VERSION 5.7 ;
BUSBITCHARS "[]" ;
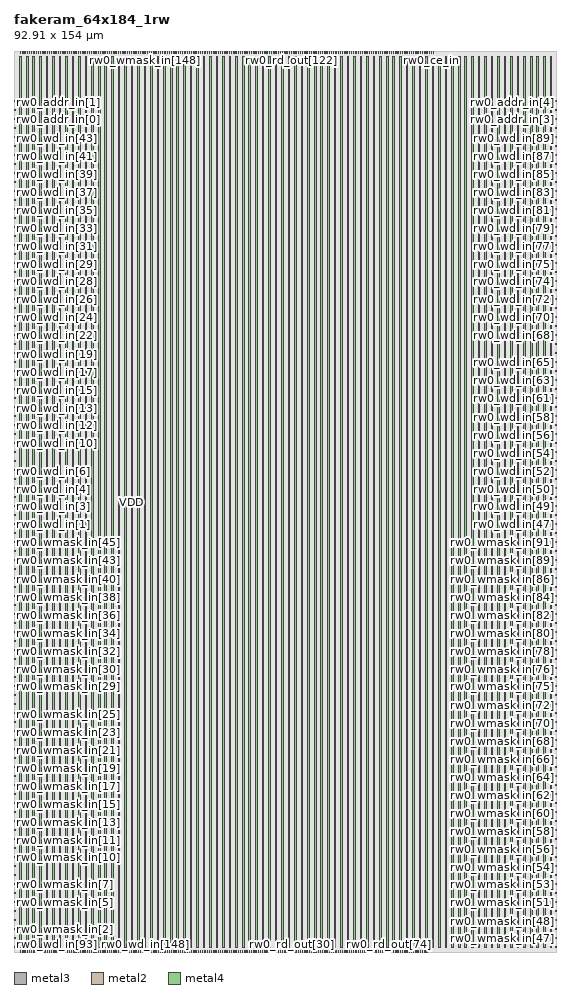
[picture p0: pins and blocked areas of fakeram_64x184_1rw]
MACRO fakeram_64x184_1rw
  FOREIGN fakeram_64x184_1rw 0 0 ;
  SYMMETRY X Y R90 ;
  SIZE 92.910 BY 154.000 ;
  CLASS BLOCK ;
  PIN rw0_wmask_in[0]
    DIRECTION INPUT ;
    USE SIGNAL ;
    SHAPE ABUTMENT ;
    PORT
      LAYER metal3 ;
      RECT 0.000 0.805 0.210 0.875 ;
    END
  END rw0_wmask_in[0]
  PIN rw0_wmask_in[1]
    DIRECTION INPUT ;
    USE SIGNAL ;
    SHAPE ABUTMENT ;
    PORT
      LAYER metal3 ;
      RECT 0.000 2.345 0.210 2.415 ;
    END
  END rw0_wmask_in[1]
  PIN rw0_wmask_in[2]
    DIRECTION INPUT ;
    USE SIGNAL ;
    SHAPE ABUTMENT ;
    PORT
      LAYER metal3 ;
      RECT 0.000 3.885 0.210 3.955 ;
    END
  END rw0_wmask_in[2]
  PIN rw0_wmask_in[3]
    DIRECTION INPUT ;
    USE SIGNAL ;
    SHAPE ABUTMENT ;
    PORT
      LAYER metal3 ;
      RECT 0.000 5.425 0.210 5.495 ;
    END
  END rw0_wmask_in[3]
  PIN rw0_wmask_in[4]
    DIRECTION INPUT ;
    USE SIGNAL ;
    SHAPE ABUTMENT ;
    PORT
      LAYER metal3 ;
      RECT 0.000 6.965 0.210 7.035 ;
    END
  END rw0_wmask_in[4]
  PIN rw0_wmask_in[5]
    DIRECTION INPUT ;
    USE SIGNAL ;
    SHAPE ABUTMENT ;
    PORT
      LAYER metal3 ;
      RECT 0.000 8.505 0.210 8.575 ;
    END
  END rw0_wmask_in[5]
  PIN rw0_wmask_in[6]
    DIRECTION INPUT ;
    USE SIGNAL ;
    SHAPE ABUTMENT ;
    PORT
      LAYER metal3 ;
      RECT 0.000 10.045 0.210 10.115 ;
    END
  END rw0_wmask_in[6]
  PIN rw0_wmask_in[7]
    DIRECTION INPUT ;
    USE SIGNAL ;
    SHAPE ABUTMENT ;
    PORT
      LAYER metal3 ;
      RECT 0.000 11.585 0.210 11.655 ;
    END
  END rw0_wmask_in[7]
  PIN rw0_wmask_in[8]
    DIRECTION INPUT ;
    USE SIGNAL ;
    SHAPE ABUTMENT ;
    PORT
      LAYER metal3 ;
      RECT 0.000 13.125 0.210 13.195 ;
    END
  END rw0_wmask_in[8]
  PIN rw0_wmask_in[9]
    DIRECTION INPUT ;
    USE SIGNAL ;
    SHAPE ABUTMENT ;
    PORT
      LAYER metal3 ;
      RECT 0.000 14.665 0.210 14.735 ;
    END
  END rw0_wmask_in[9]
  PIN rw0_wmask_in[10]
    DIRECTION INPUT ;
    USE SIGNAL ;
    SHAPE ABUTMENT ;
    PORT
      LAYER metal3 ;
      RECT 0.000 16.205 0.210 16.275 ;
    END
  END rw0_wmask_in[10]
  PIN rw0_wmask_in[11]
    DIRECTION INPUT ;
    USE SIGNAL ;
    SHAPE ABUTMENT ;
    PORT
      LAYER metal3 ;
      RECT 0.000 17.745 0.210 17.815 ;
    END
  END rw0_wmask_in[11]
  PIN rw0_wmask_in[12]
    DIRECTION INPUT ;
    USE SIGNAL ;
    SHAPE ABUTMENT ;
    PORT
      LAYER metal3 ;
      RECT 0.000 19.285 0.210 19.355 ;
    END
  END rw0_wmask_in[12]
  PIN rw0_wmask_in[13]
    DIRECTION INPUT ;
    USE SIGNAL ;
    SHAPE ABUTMENT ;
    PORT
      LAYER metal3 ;
      RECT 0.000 20.825 0.210 20.895 ;
    END
  END rw0_wmask_in[13]
  PIN rw0_wmask_in[14]
    DIRECTION INPUT ;
    USE SIGNAL ;
    SHAPE ABUTMENT ;
    PORT
      LAYER metal3 ;
      RECT 0.000 22.365 0.210 22.435 ;
    END
  END rw0_wmask_in[14]
  PIN rw0_wmask_in[15]
    DIRECTION INPUT ;
    USE SIGNAL ;
    SHAPE ABUTMENT ;
    PORT
      LAYER metal3 ;
      RECT 0.000 23.905 0.210 23.975 ;
    END
  END rw0_wmask_in[15]
  PIN rw0_wmask_in[16]
    DIRECTION INPUT ;
    USE SIGNAL ;
    SHAPE ABUTMENT ;
    PORT
      LAYER metal3 ;
      RECT 0.000 25.445 0.210 25.515 ;
    END
  END rw0_wmask_in[16]
  PIN rw0_wmask_in[17]
    DIRECTION INPUT ;
    USE SIGNAL ;
    SHAPE ABUTMENT ;
    PORT
      LAYER metal3 ;
      RECT 0.000 26.985 0.210 27.055 ;
    END
  END rw0_wmask_in[17]
  PIN rw0_wmask_in[18]
    DIRECTION INPUT ;
    USE SIGNAL ;
    SHAPE ABUTMENT ;
    PORT
      LAYER metal3 ;
      RECT 0.000 28.525 0.210 28.595 ;
    END
  END rw0_wmask_in[18]
  PIN rw0_wmask_in[19]
    DIRECTION INPUT ;
    USE SIGNAL ;
    SHAPE ABUTMENT ;
    PORT
      LAYER metal3 ;
      RECT 0.000 30.065 0.210 30.135 ;
    END
  END rw0_wmask_in[19]
  PIN rw0_wmask_in[20]
    DIRECTION INPUT ;
    USE SIGNAL ;
    SHAPE ABUTMENT ;
    PORT
      LAYER metal3 ;
      RECT 0.000 31.605 0.210 31.675 ;
    END
  END rw0_wmask_in[20]
  PIN rw0_wmask_in[21]
    DIRECTION INPUT ;
    USE SIGNAL ;
    SHAPE ABUTMENT ;
    PORT
      LAYER metal3 ;
      RECT 0.000 33.145 0.210 33.215 ;
    END
  END rw0_wmask_in[21]
  PIN rw0_wmask_in[22]
    DIRECTION INPUT ;
    USE SIGNAL ;
    SHAPE ABUTMENT ;
    PORT
      LAYER metal3 ;
      RECT 0.000 34.685 0.210 34.755 ;
    END
  END rw0_wmask_in[22]
  PIN rw0_wmask_in[23]
    DIRECTION INPUT ;
    USE SIGNAL ;
    SHAPE ABUTMENT ;
    PORT
      LAYER metal3 ;
      RECT 0.000 36.225 0.210 36.295 ;
    END
  END rw0_wmask_in[23]
  PIN rw0_wmask_in[24]
    DIRECTION INPUT ;
    USE SIGNAL ;
    SHAPE ABUTMENT ;
    PORT
      LAYER metal3 ;
      RECT 0.000 37.765 0.210 37.835 ;
    END
  END rw0_wmask_in[24]
  PIN rw0_wmask_in[25]
    DIRECTION INPUT ;
    USE SIGNAL ;
    SHAPE ABUTMENT ;
    PORT
      LAYER metal3 ;
      RECT 0.000 39.305 0.210 39.375 ;
    END
  END rw0_wmask_in[25]
  PIN rw0_wmask_in[26]
    DIRECTION INPUT ;
    USE SIGNAL ;
    SHAPE ABUTMENT ;
    PORT
      LAYER metal3 ;
      RECT 0.000 40.845 0.210 40.915 ;
    END
  END rw0_wmask_in[26]
  PIN rw0_wmask_in[27]
    DIRECTION INPUT ;
    USE SIGNAL ;
    SHAPE ABUTMENT ;
    PORT
      LAYER metal3 ;
      RECT 0.000 42.385 0.210 42.455 ;
    END
  END rw0_wmask_in[27]
  PIN rw0_wmask_in[28]
    DIRECTION INPUT ;
    USE SIGNAL ;
    SHAPE ABUTMENT ;
    PORT
      LAYER metal3 ;
      RECT 0.000 43.925 0.210 43.995 ;
    END
  END rw0_wmask_in[28]
  PIN rw0_wmask_in[29]
    DIRECTION INPUT ;
    USE SIGNAL ;
    SHAPE ABUTMENT ;
    PORT
      LAYER metal3 ;
      RECT 0.000 45.465 0.210 45.535 ;
    END
  END rw0_wmask_in[29]
  PIN rw0_wmask_in[30]
    DIRECTION INPUT ;
    USE SIGNAL ;
    SHAPE ABUTMENT ;
    PORT
      LAYER metal3 ;
      RECT 0.000 47.005 0.210 47.075 ;
    END
  END rw0_wmask_in[30]
  PIN rw0_wmask_in[31]
    DIRECTION INPUT ;
    USE SIGNAL ;
    SHAPE ABUTMENT ;
    PORT
      LAYER metal3 ;
      RECT 0.000 48.545 0.210 48.615 ;
    END
  END rw0_wmask_in[31]
  PIN rw0_wmask_in[32]
    DIRECTION INPUT ;
    USE SIGNAL ;
    SHAPE ABUTMENT ;
    PORT
      LAYER metal3 ;
      RECT 0.000 50.085 0.210 50.155 ;
    END
  END rw0_wmask_in[32]
  PIN rw0_wmask_in[33]
    DIRECTION INPUT ;
    USE SIGNAL ;
    SHAPE ABUTMENT ;
    PORT
      LAYER metal3 ;
      RECT 0.000 51.625 0.210 51.695 ;
    END
  END rw0_wmask_in[33]
  PIN rw0_wmask_in[34]
    DIRECTION INPUT ;
    USE SIGNAL ;
    SHAPE ABUTMENT ;
    PORT
      LAYER metal3 ;
      RECT 0.000 53.165 0.210 53.235 ;
    END
  END rw0_wmask_in[34]
  PIN rw0_wmask_in[35]
    DIRECTION INPUT ;
    USE SIGNAL ;
    SHAPE ABUTMENT ;
    PORT
      LAYER metal3 ;
      RECT 0.000 54.705 0.210 54.775 ;
    END
  END rw0_wmask_in[35]
  PIN rw0_wmask_in[36]
    DIRECTION INPUT ;
    USE SIGNAL ;
    SHAPE ABUTMENT ;
    PORT
      LAYER metal3 ;
      RECT 0.000 56.245 0.210 56.315 ;
    END
  END rw0_wmask_in[36]
  PIN rw0_wmask_in[37]
    DIRECTION INPUT ;
    USE SIGNAL ;
    SHAPE ABUTMENT ;
    PORT
      LAYER metal3 ;
      RECT 0.000 57.785 0.210 57.855 ;
    END
  END rw0_wmask_in[37]
  PIN rw0_wmask_in[38]
    DIRECTION INPUT ;
    USE SIGNAL ;
    SHAPE ABUTMENT ;
    PORT
      LAYER metal3 ;
      RECT 0.000 59.325 0.210 59.395 ;
    END
  END rw0_wmask_in[38]
  PIN rw0_wmask_in[39]
    DIRECTION INPUT ;
    USE SIGNAL ;
    SHAPE ABUTMENT ;
    PORT
      LAYER metal3 ;
      RECT 0.000 60.865 0.210 60.935 ;
    END
  END rw0_wmask_in[39]
  PIN rw0_wmask_in[40]
    DIRECTION INPUT ;
    USE SIGNAL ;
    SHAPE ABUTMENT ;
    PORT
      LAYER metal3 ;
      RECT 0.000 62.405 0.210 62.475 ;
    END
  END rw0_wmask_in[40]
  PIN rw0_wmask_in[41]
    DIRECTION INPUT ;
    USE SIGNAL ;
    SHAPE ABUTMENT ;
    PORT
      LAYER metal3 ;
      RECT 0.000 63.945 0.210 64.015 ;
    END
  END rw0_wmask_in[41]
  PIN rw0_wmask_in[42]
    DIRECTION INPUT ;
    USE SIGNAL ;
    SHAPE ABUTMENT ;
    PORT
      LAYER metal3 ;
      RECT 0.000 65.485 0.210 65.555 ;
    END
  END rw0_wmask_in[42]
  PIN rw0_wmask_in[43]
    DIRECTION INPUT ;
    USE SIGNAL ;
    SHAPE ABUTMENT ;
    PORT
      LAYER metal3 ;
      RECT 0.000 67.025 0.210 67.095 ;
    END
  END rw0_wmask_in[43]
  PIN rw0_wmask_in[44]
    DIRECTION INPUT ;
    USE SIGNAL ;
    SHAPE ABUTMENT ;
    PORT
      LAYER metal3 ;
      RECT 0.000 68.565 0.210 68.635 ;
    END
  END rw0_wmask_in[44]
  PIN rw0_wmask_in[45]
    DIRECTION INPUT ;
    USE SIGNAL ;
    SHAPE ABUTMENT ;
    PORT
      LAYER metal3 ;
      RECT 0.000 70.105 0.210 70.175 ;
    END
  END rw0_wmask_in[45]
  PIN rw0_wmask_in[46]
    DIRECTION INPUT ;
    USE SIGNAL ;
    SHAPE ABUTMENT ;
    PORT
      LAYER metal3 ;
      RECT 92.700 0.805 92.910 0.875 ;
    END
  END rw0_wmask_in[46]
  PIN rw0_wmask_in[47]
    DIRECTION INPUT ;
    USE SIGNAL ;
    SHAPE ABUTMENT ;
    PORT
      LAYER metal3 ;
      RECT 92.700 2.345 92.910 2.415 ;
    END
  END rw0_wmask_in[47]
  PIN rw0_wmask_in[48]
    DIRECTION INPUT ;
    USE SIGNAL ;
    SHAPE ABUTMENT ;
    PORT
      LAYER metal3 ;
      RECT 92.700 3.885 92.910 3.955 ;
    END
  END rw0_wmask_in[48]
  PIN rw0_wmask_in[49]
    DIRECTION INPUT ;
    USE SIGNAL ;
    SHAPE ABUTMENT ;
    PORT
      LAYER metal3 ;
      RECT 92.700 5.425 92.910 5.495 ;
    END
  END rw0_wmask_in[49]
  PIN rw0_wmask_in[50]
    DIRECTION INPUT ;
    USE SIGNAL ;
    SHAPE ABUTMENT ;
    PORT
      LAYER metal3 ;
      RECT 92.700 6.965 92.910 7.035 ;
    END
  END rw0_wmask_in[50]
  PIN rw0_wmask_in[51]
    DIRECTION INPUT ;
    USE SIGNAL ;
    SHAPE ABUTMENT ;
    PORT
      LAYER metal3 ;
      RECT 92.700 8.505 92.910 8.575 ;
    END
  END rw0_wmask_in[51]
  PIN rw0_wmask_in[52]
    DIRECTION INPUT ;
    USE SIGNAL ;
    SHAPE ABUTMENT ;
    PORT
      LAYER metal3 ;
      RECT 92.700 10.045 92.910 10.115 ;
    END
  END rw0_wmask_in[52]
  PIN rw0_wmask_in[53]
    DIRECTION INPUT ;
    USE SIGNAL ;
    SHAPE ABUTMENT ;
    PORT
      LAYER metal3 ;
      RECT 92.700 11.585 92.910 11.655 ;
    END
  END rw0_wmask_in[53]
  PIN rw0_wmask_in[54]
    DIRECTION INPUT ;
    USE SIGNAL ;
    SHAPE ABUTMENT ;
    PORT
      LAYER metal3 ;
      RECT 92.700 13.125 92.910 13.195 ;
    END
  END rw0_wmask_in[54]
  PIN rw0_wmask_in[55]
    DIRECTION INPUT ;
    USE SIGNAL ;
    SHAPE ABUTMENT ;
    PORT
      LAYER metal3 ;
      RECT 92.700 14.665 92.910 14.735 ;
    END
  END rw0_wmask_in[55]
  PIN rw0_wmask_in[56]
    DIRECTION INPUT ;
    USE SIGNAL ;
    SHAPE ABUTMENT ;
    PORT
      LAYER metal3 ;
      RECT 92.700 16.205 92.910 16.275 ;
    END
  END rw0_wmask_in[56]
  PIN rw0_wmask_in[57]
    DIRECTION INPUT ;
    USE SIGNAL ;
    SHAPE ABUTMENT ;
    PORT
      LAYER metal3 ;
      RECT 92.700 17.745 92.910 17.815 ;
    END
  END rw0_wmask_in[57]
  PIN rw0_wmask_in[58]
    DIRECTION INPUT ;
    USE SIGNAL ;
    SHAPE ABUTMENT ;
    PORT
      LAYER metal3 ;
      RECT 92.700 19.285 92.910 19.355 ;
    END
  END rw0_wmask_in[58]
  PIN rw0_wmask_in[59]
    DIRECTION INPUT ;
    USE SIGNAL ;
    SHAPE ABUTMENT ;
    PORT
      LAYER metal3 ;
      RECT 92.700 20.825 92.910 20.895 ;
    END
  END rw0_wmask_in[59]
  PIN rw0_wmask_in[60]
    DIRECTION INPUT ;
    USE SIGNAL ;
    SHAPE ABUTMENT ;
    PORT
      LAYER metal3 ;
      RECT 92.700 22.365 92.910 22.435 ;
    END
  END rw0_wmask_in[60]
  PIN rw0_wmask_in[61]
    DIRECTION INPUT ;
    USE SIGNAL ;
    SHAPE ABUTMENT ;
    PORT
      LAYER metal3 ;
      RECT 92.700 23.905 92.910 23.975 ;
    END
  END rw0_wmask_in[61]
  PIN rw0_wmask_in[62]
    DIRECTION INPUT ;
    USE SIGNAL ;
    SHAPE ABUTMENT ;
    PORT
      LAYER metal3 ;
      RECT 92.700 25.445 92.910 25.515 ;
    END
  END rw0_wmask_in[62]
  PIN rw0_wmask_in[63]
    DIRECTION INPUT ;
    USE SIGNAL ;
    SHAPE ABUTMENT ;
    PORT
      LAYER metal3 ;
      RECT 92.700 26.985 92.910 27.055 ;
    END
  END rw0_wmask_in[63]
  PIN rw0_wmask_in[64]
    DIRECTION INPUT ;
    USE SIGNAL ;
    SHAPE ABUTMENT ;
    PORT
      LAYER metal3 ;
      RECT 92.700 28.525 92.910 28.595 ;
    END
  END rw0_wmask_in[64]
  PIN rw0_wmask_in[65]
    DIRECTION INPUT ;
    USE SIGNAL ;
    SHAPE ABUTMENT ;
    PORT
      LAYER metal3 ;
      RECT 92.700 30.065 92.910 30.135 ;
    END
  END rw0_wmask_in[65]
  PIN rw0_wmask_in[66]
    DIRECTION INPUT ;
    USE SIGNAL ;
    SHAPE ABUTMENT ;
    PORT
      LAYER metal3 ;
      RECT 92.700 31.605 92.910 31.675 ;
    END
  END rw0_wmask_in[66]
  PIN rw0_wmask_in[67]
    DIRECTION INPUT ;
    USE SIGNAL ;
    SHAPE ABUTMENT ;
    PORT
      LAYER metal3 ;
      RECT 92.700 33.145 92.910 33.215 ;
    END
  END rw0_wmask_in[67]
  PIN rw0_wmask_in[68]
    DIRECTION INPUT ;
    USE SIGNAL ;
    SHAPE ABUTMENT ;
    PORT
      LAYER metal3 ;
      RECT 92.700 34.685 92.910 34.755 ;
    END
  END rw0_wmask_in[68]
  PIN rw0_wmask_in[69]
    DIRECTION INPUT ;
    USE SIGNAL ;
    SHAPE ABUTMENT ;
    PORT
      LAYER metal3 ;
      RECT 92.700 36.225 92.910 36.295 ;
    END
  END rw0_wmask_in[69]
  PIN rw0_wmask_in[70]
    DIRECTION INPUT ;
    USE SIGNAL ;
    SHAPE ABUTMENT ;
    PORT
      LAYER metal3 ;
      RECT 92.700 37.765 92.910 37.835 ;
    END
  END rw0_wmask_in[70]
  PIN rw0_wmask_in[71]
    DIRECTION INPUT ;
    USE SIGNAL ;
    SHAPE ABUTMENT ;
    PORT
      LAYER metal3 ;
      RECT 92.700 39.305 92.910 39.375 ;
    END
  END rw0_wmask_in[71]
  PIN rw0_wmask_in[72]
    DIRECTION INPUT ;
    USE SIGNAL ;
    SHAPE ABUTMENT ;
    PORT
      LAYER metal3 ;
      RECT 92.700 40.845 92.910 40.915 ;
    END
  END rw0_wmask_in[72]
  PIN rw0_wmask_in[73]
    DIRECTION INPUT ;
    USE SIGNAL ;
    SHAPE ABUTMENT ;
    PORT
      LAYER metal3 ;
      RECT 92.700 42.385 92.910 42.455 ;
    END
  END rw0_wmask_in[73]
  PIN rw0_wmask_in[74]
    DIRECTION INPUT ;
    USE SIGNAL ;
    SHAPE ABUTMENT ;
    PORT
      LAYER metal3 ;
      RECT 92.700 43.925 92.910 43.995 ;
    END
  END rw0_wmask_in[74]
  PIN rw0_wmask_in[75]
    DIRECTION INPUT ;
    USE SIGNAL ;
    SHAPE ABUTMENT ;
    PORT
      LAYER metal3 ;
      RECT 92.700 45.465 92.910 45.535 ;
    END
  END rw0_wmask_in[75]
  PIN rw0_wmask_in[76]
    DIRECTION INPUT ;
    USE SIGNAL ;
    SHAPE ABUTMENT ;
    PORT
      LAYER metal3 ;
      RECT 92.700 47.005 92.910 47.075 ;
    END
  END rw0_wmask_in[76]
  PIN rw0_wmask_in[77]
    DIRECTION INPUT ;
    USE SIGNAL ;
    SHAPE ABUTMENT ;
    PORT
      LAYER metal3 ;
      RECT 92.700 48.545 92.910 48.615 ;
    END
  END rw0_wmask_in[77]
  PIN rw0_wmask_in[78]
    DIRECTION INPUT ;
    USE SIGNAL ;
    SHAPE ABUTMENT ;
    PORT
      LAYER metal3 ;
      RECT 92.700 50.085 92.910 50.155 ;
    END
  END rw0_wmask_in[78]
  PIN rw0_wmask_in[79]
    DIRECTION INPUT ;
    USE SIGNAL ;
    SHAPE ABUTMENT ;
    PORT
      LAYER metal3 ;
      RECT 92.700 51.625 92.910 51.695 ;
    END
  END rw0_wmask_in[79]
  PIN rw0_wmask_in[80]
    DIRECTION INPUT ;
    USE SIGNAL ;
    SHAPE ABUTMENT ;
    PORT
      LAYER metal3 ;
      RECT 92.700 53.165 92.910 53.235 ;
    END
  END rw0_wmask_in[80]
  PIN rw0_wmask_in[81]
    DIRECTION INPUT ;
    USE SIGNAL ;
    SHAPE ABUTMENT ;
    PORT
      LAYER metal3 ;
      RECT 92.700 54.705 92.910 54.775 ;
    END
  END rw0_wmask_in[81]
  PIN rw0_wmask_in[82]
    DIRECTION INPUT ;
    USE SIGNAL ;
    SHAPE ABUTMENT ;
    PORT
      LAYER metal3 ;
      RECT 92.700 56.245 92.910 56.315 ;
    END
  END rw0_wmask_in[82]
  PIN rw0_wmask_in[83]
    DIRECTION INPUT ;
    USE SIGNAL ;
    SHAPE ABUTMENT ;
    PORT
      LAYER metal3 ;
      RECT 92.700 57.785 92.910 57.855 ;
    END
  END rw0_wmask_in[83]
  PIN rw0_wmask_in[84]
    DIRECTION INPUT ;
    USE SIGNAL ;
    SHAPE ABUTMENT ;
    PORT
      LAYER metal3 ;
      RECT 92.700 59.325 92.910 59.395 ;
    END
  END rw0_wmask_in[84]
  PIN rw0_wmask_in[85]
    DIRECTION INPUT ;
    USE SIGNAL ;
    SHAPE ABUTMENT ;
    PORT
      LAYER metal3 ;
      RECT 92.700 60.865 92.910 60.935 ;
    END
  END rw0_wmask_in[85]
  PIN rw0_wmask_in[86]
    DIRECTION INPUT ;
    USE SIGNAL ;
    SHAPE ABUTMENT ;
    PORT
      LAYER metal3 ;
      RECT 92.700 62.405 92.910 62.475 ;
    END
  END rw0_wmask_in[86]
  PIN rw0_wmask_in[87]
    DIRECTION INPUT ;
    USE SIGNAL ;
    SHAPE ABUTMENT ;
    PORT
      LAYER metal3 ;
      RECT 92.700 63.945 92.910 64.015 ;
    END
  END rw0_wmask_in[87]
  PIN rw0_wmask_in[88]
    DIRECTION INPUT ;
    USE SIGNAL ;
    SHAPE ABUTMENT ;
    PORT
      LAYER metal3 ;
      RECT 92.700 65.485 92.910 65.555 ;
    END
  END rw0_wmask_in[88]
  PIN rw0_wmask_in[89]
    DIRECTION INPUT ;
    USE SIGNAL ;
    SHAPE ABUTMENT ;
    PORT
      LAYER metal3 ;
      RECT 92.700 67.025 92.910 67.095 ;
    END
  END rw0_wmask_in[89]
  PIN rw0_wmask_in[90]
    DIRECTION INPUT ;
    USE SIGNAL ;
    SHAPE ABUTMENT ;
    PORT
      LAYER metal3 ;
      RECT 92.700 68.565 92.910 68.635 ;
    END
  END rw0_wmask_in[90]
  PIN rw0_wmask_in[91]
    DIRECTION INPUT ;
    USE SIGNAL ;
    SHAPE ABUTMENT ;
    PORT
      LAYER metal3 ;
      RECT 92.700 70.105 92.910 70.175 ;
    END
  END rw0_wmask_in[91]
  PIN rw0_wmask_in[92]
    DIRECTION INPUT ;
    USE SIGNAL ;
    SHAPE ABUTMENT ;
    PORT
      LAYER metal2 ;
      RECT 1.105 153.790 1.175 154.000 ;
    END
  END rw0_wmask_in[92]
  PIN rw0_wmask_in[93]
    DIRECTION INPUT ;
    USE SIGNAL ;
    SHAPE ABUTMENT ;
    PORT
      LAYER metal2 ;
      RECT 1.485 153.790 1.555 154.000 ;
    END
  END rw0_wmask_in[93]
  PIN rw0_wmask_in[94]
    DIRECTION INPUT ;
    USE SIGNAL ;
    SHAPE ABUTMENT ;
    PORT
      LAYER metal2 ;
      RECT 1.865 153.790 1.935 154.000 ;
    END
  END rw0_wmask_in[94]
  PIN rw0_wmask_in[95]
    DIRECTION INPUT ;
    USE SIGNAL ;
    SHAPE ABUTMENT ;
    PORT
      LAYER metal2 ;
      RECT 2.245 153.790 2.315 154.000 ;
    END
  END rw0_wmask_in[95]
  PIN rw0_wmask_in[96]
    DIRECTION INPUT ;
    USE SIGNAL ;
    SHAPE ABUTMENT ;
    PORT
      LAYER metal2 ;
      RECT 2.625 153.790 2.695 154.000 ;
    END
  END rw0_wmask_in[96]
  PIN rw0_wmask_in[97]
    DIRECTION INPUT ;
    USE SIGNAL ;
    SHAPE ABUTMENT ;
    PORT
      LAYER metal2 ;
      RECT 3.005 153.790 3.075 154.000 ;
    END
  END rw0_wmask_in[97]
  PIN rw0_wmask_in[98]
    DIRECTION INPUT ;
    USE SIGNAL ;
    SHAPE ABUTMENT ;
    PORT
      LAYER metal2 ;
      RECT 3.385 153.790 3.455 154.000 ;
    END
  END rw0_wmask_in[98]
  PIN rw0_wmask_in[99]
    DIRECTION INPUT ;
    USE SIGNAL ;
    SHAPE ABUTMENT ;
    PORT
      LAYER metal2 ;
      RECT 3.765 153.790 3.835 154.000 ;
    END
  END rw0_wmask_in[99]
  PIN rw0_wmask_in[100]
    DIRECTION INPUT ;
    USE SIGNAL ;
    SHAPE ABUTMENT ;
    PORT
      LAYER metal2 ;
      RECT 4.145 153.790 4.215 154.000 ;
    END
  END rw0_wmask_in[100]
  PIN rw0_wmask_in[101]
    DIRECTION INPUT ;
    USE SIGNAL ;
    SHAPE ABUTMENT ;
    PORT
      LAYER metal2 ;
      RECT 4.525 153.790 4.595 154.000 ;
    END
  END rw0_wmask_in[101]
  PIN rw0_wmask_in[102]
    DIRECTION INPUT ;
    USE SIGNAL ;
    SHAPE ABUTMENT ;
    PORT
      LAYER metal2 ;
      RECT 4.905 153.790 4.975 154.000 ;
    END
  END rw0_wmask_in[102]
  PIN rw0_wmask_in[103]
    DIRECTION INPUT ;
    USE SIGNAL ;
    SHAPE ABUTMENT ;
    PORT
      LAYER metal2 ;
      RECT 5.285 153.790 5.355 154.000 ;
    END
  END rw0_wmask_in[103]
  PIN rw0_wmask_in[104]
    DIRECTION INPUT ;
    USE SIGNAL ;
    SHAPE ABUTMENT ;
    PORT
      LAYER metal2 ;
      RECT 5.665 153.790 5.735 154.000 ;
    END
  END rw0_wmask_in[104]
  PIN rw0_wmask_in[105]
    DIRECTION INPUT ;
    USE SIGNAL ;
    SHAPE ABUTMENT ;
    PORT
      LAYER metal2 ;
      RECT 6.045 153.790 6.115 154.000 ;
    END
  END rw0_wmask_in[105]
  PIN rw0_wmask_in[106]
    DIRECTION INPUT ;
    USE SIGNAL ;
    SHAPE ABUTMENT ;
    PORT
      LAYER metal2 ;
      RECT 6.425 153.790 6.495 154.000 ;
    END
  END rw0_wmask_in[106]
  PIN rw0_wmask_in[107]
    DIRECTION INPUT ;
    USE SIGNAL ;
    SHAPE ABUTMENT ;
    PORT
      LAYER metal2 ;
      RECT 6.805 153.790 6.875 154.000 ;
    END
  END rw0_wmask_in[107]
  PIN rw0_wmask_in[108]
    DIRECTION INPUT ;
    USE SIGNAL ;
    SHAPE ABUTMENT ;
    PORT
      LAYER metal2 ;
      RECT 7.185 153.790 7.255 154.000 ;
    END
  END rw0_wmask_in[108]
  PIN rw0_wmask_in[109]
    DIRECTION INPUT ;
    USE SIGNAL ;
    SHAPE ABUTMENT ;
    PORT
      LAYER metal2 ;
      RECT 7.565 153.790 7.635 154.000 ;
    END
  END rw0_wmask_in[109]
  PIN rw0_wmask_in[110]
    DIRECTION INPUT ;
    USE SIGNAL ;
    SHAPE ABUTMENT ;
    PORT
      LAYER metal2 ;
      RECT 7.945 153.790 8.015 154.000 ;
    END
  END rw0_wmask_in[110]
  PIN rw0_wmask_in[111]
    DIRECTION INPUT ;
    USE SIGNAL ;
    SHAPE ABUTMENT ;
    PORT
      LAYER metal2 ;
      RECT 8.325 153.790 8.395 154.000 ;
    END
  END rw0_wmask_in[111]
  PIN rw0_wmask_in[112]
    DIRECTION INPUT ;
    USE SIGNAL ;
    SHAPE ABUTMENT ;
    PORT
      LAYER metal2 ;
      RECT 8.705 153.790 8.775 154.000 ;
    END
  END rw0_wmask_in[112]
  PIN rw0_wmask_in[113]
    DIRECTION INPUT ;
    USE SIGNAL ;
    SHAPE ABUTMENT ;
    PORT
      LAYER metal2 ;
      RECT 9.085 153.790 9.155 154.000 ;
    END
  END rw0_wmask_in[113]
  PIN rw0_wmask_in[114]
    DIRECTION INPUT ;
    USE SIGNAL ;
    SHAPE ABUTMENT ;
    PORT
      LAYER metal2 ;
      RECT 9.465 153.790 9.535 154.000 ;
    END
  END rw0_wmask_in[114]
  PIN rw0_wmask_in[115]
    DIRECTION INPUT ;
    USE SIGNAL ;
    SHAPE ABUTMENT ;
    PORT
      LAYER metal2 ;
      RECT 9.845 153.790 9.915 154.000 ;
    END
  END rw0_wmask_in[115]
  PIN rw0_wmask_in[116]
    DIRECTION INPUT ;
    USE SIGNAL ;
    SHAPE ABUTMENT ;
    PORT
      LAYER metal2 ;
      RECT 10.225 153.790 10.295 154.000 ;
    END
  END rw0_wmask_in[116]
  PIN rw0_wmask_in[117]
    DIRECTION INPUT ;
    USE SIGNAL ;
    SHAPE ABUTMENT ;
    PORT
      LAYER metal2 ;
      RECT 10.605 153.790 10.675 154.000 ;
    END
  END rw0_wmask_in[117]
  PIN rw0_wmask_in[118]
    DIRECTION INPUT ;
    USE SIGNAL ;
    SHAPE ABUTMENT ;
    PORT
      LAYER metal2 ;
      RECT 10.985 153.790 11.055 154.000 ;
    END
  END rw0_wmask_in[118]
  PIN rw0_wmask_in[119]
    DIRECTION INPUT ;
    USE SIGNAL ;
    SHAPE ABUTMENT ;
    PORT
      LAYER metal2 ;
      RECT 11.365 153.790 11.435 154.000 ;
    END
  END rw0_wmask_in[119]
  PIN rw0_wmask_in[120]
    DIRECTION INPUT ;
    USE SIGNAL ;
    SHAPE ABUTMENT ;
    PORT
      LAYER metal2 ;
      RECT 11.745 153.790 11.815 154.000 ;
    END
  END rw0_wmask_in[120]
  PIN rw0_wmask_in[121]
    DIRECTION INPUT ;
    USE SIGNAL ;
    SHAPE ABUTMENT ;
    PORT
      LAYER metal2 ;
      RECT 12.125 153.790 12.195 154.000 ;
    END
  END rw0_wmask_in[121]
  PIN rw0_wmask_in[122]
    DIRECTION INPUT ;
    USE SIGNAL ;
    SHAPE ABUTMENT ;
    PORT
      LAYER metal2 ;
      RECT 12.505 153.790 12.575 154.000 ;
    END
  END rw0_wmask_in[122]
  PIN rw0_wmask_in[123]
    DIRECTION INPUT ;
    USE SIGNAL ;
    SHAPE ABUTMENT ;
    PORT
      LAYER metal2 ;
      RECT 12.885 153.790 12.955 154.000 ;
    END
  END rw0_wmask_in[123]
  PIN rw0_wmask_in[124]
    DIRECTION INPUT ;
    USE SIGNAL ;
    SHAPE ABUTMENT ;
    PORT
      LAYER metal2 ;
      RECT 13.265 153.790 13.335 154.000 ;
    END
  END rw0_wmask_in[124]
  PIN rw0_wmask_in[125]
    DIRECTION INPUT ;
    USE SIGNAL ;
    SHAPE ABUTMENT ;
    PORT
      LAYER metal2 ;
      RECT 13.645 153.790 13.715 154.000 ;
    END
  END rw0_wmask_in[125]
  PIN rw0_wmask_in[126]
    DIRECTION INPUT ;
    USE SIGNAL ;
    SHAPE ABUTMENT ;
    PORT
      LAYER metal2 ;
      RECT 14.025 153.790 14.095 154.000 ;
    END
  END rw0_wmask_in[126]
  PIN rw0_wmask_in[127]
    DIRECTION INPUT ;
    USE SIGNAL ;
    SHAPE ABUTMENT ;
    PORT
      LAYER metal2 ;
      RECT 14.405 153.790 14.475 154.000 ;
    END
  END rw0_wmask_in[127]
  PIN rw0_wmask_in[128]
    DIRECTION INPUT ;
    USE SIGNAL ;
    SHAPE ABUTMENT ;
    PORT
      LAYER metal2 ;
      RECT 14.785 153.790 14.855 154.000 ;
    END
  END rw0_wmask_in[128]
  PIN rw0_wmask_in[129]
    DIRECTION INPUT ;
    USE SIGNAL ;
    SHAPE ABUTMENT ;
    PORT
      LAYER metal2 ;
      RECT 15.165 153.790 15.235 154.000 ;
    END
  END rw0_wmask_in[129]
  PIN rw0_wmask_in[130]
    DIRECTION INPUT ;
    USE SIGNAL ;
    SHAPE ABUTMENT ;
    PORT
      LAYER metal2 ;
      RECT 15.545 153.790 15.615 154.000 ;
    END
  END rw0_wmask_in[130]
  PIN rw0_wmask_in[131]
    DIRECTION INPUT ;
    USE SIGNAL ;
    SHAPE ABUTMENT ;
    PORT
      LAYER metal2 ;
      RECT 15.925 153.790 15.995 154.000 ;
    END
  END rw0_wmask_in[131]
  PIN rw0_wmask_in[132]
    DIRECTION INPUT ;
    USE SIGNAL ;
    SHAPE ABUTMENT ;
    PORT
      LAYER metal2 ;
      RECT 16.305 153.790 16.375 154.000 ;
    END
  END rw0_wmask_in[132]
  PIN rw0_wmask_in[133]
    DIRECTION INPUT ;
    USE SIGNAL ;
    SHAPE ABUTMENT ;
    PORT
      LAYER metal2 ;
      RECT 16.685 153.790 16.755 154.000 ;
    END
  END rw0_wmask_in[133]
  PIN rw0_wmask_in[134]
    DIRECTION INPUT ;
    USE SIGNAL ;
    SHAPE ABUTMENT ;
    PORT
      LAYER metal2 ;
      RECT 17.065 153.790 17.135 154.000 ;
    END
  END rw0_wmask_in[134]
  PIN rw0_wmask_in[135]
    DIRECTION INPUT ;
    USE SIGNAL ;
    SHAPE ABUTMENT ;
    PORT
      LAYER metal2 ;
      RECT 17.445 153.790 17.515 154.000 ;
    END
  END rw0_wmask_in[135]
  PIN rw0_wmask_in[136]
    DIRECTION INPUT ;
    USE SIGNAL ;
    SHAPE ABUTMENT ;
    PORT
      LAYER metal2 ;
      RECT 17.825 153.790 17.895 154.000 ;
    END
  END rw0_wmask_in[136]
  PIN rw0_wmask_in[137]
    DIRECTION INPUT ;
    USE SIGNAL ;
    SHAPE ABUTMENT ;
    PORT
      LAYER metal2 ;
      RECT 18.205 153.790 18.275 154.000 ;
    END
  END rw0_wmask_in[137]
  PIN rw0_wmask_in[138]
    DIRECTION INPUT ;
    USE SIGNAL ;
    SHAPE ABUTMENT ;
    PORT
      LAYER metal2 ;
      RECT 18.585 153.790 18.655 154.000 ;
    END
  END rw0_wmask_in[138]
  PIN rw0_wmask_in[139]
    DIRECTION INPUT ;
    USE SIGNAL ;
    SHAPE ABUTMENT ;
    PORT
      LAYER metal2 ;
      RECT 18.965 153.790 19.035 154.000 ;
    END
  END rw0_wmask_in[139]
  PIN rw0_wmask_in[140]
    DIRECTION INPUT ;
    USE SIGNAL ;
    SHAPE ABUTMENT ;
    PORT
      LAYER metal2 ;
      RECT 19.345 153.790 19.415 154.000 ;
    END
  END rw0_wmask_in[140]
  PIN rw0_wmask_in[141]
    DIRECTION INPUT ;
    USE SIGNAL ;
    SHAPE ABUTMENT ;
    PORT
      LAYER metal2 ;
      RECT 19.725 153.790 19.795 154.000 ;
    END
  END rw0_wmask_in[141]
  PIN rw0_wmask_in[142]
    DIRECTION INPUT ;
    USE SIGNAL ;
    SHAPE ABUTMENT ;
    PORT
      LAYER metal2 ;
      RECT 20.105 153.790 20.175 154.000 ;
    END
  END rw0_wmask_in[142]
  PIN rw0_wmask_in[143]
    DIRECTION INPUT ;
    USE SIGNAL ;
    SHAPE ABUTMENT ;
    PORT
      LAYER metal2 ;
      RECT 20.485 153.790 20.555 154.000 ;
    END
  END rw0_wmask_in[143]
  PIN rw0_wmask_in[144]
    DIRECTION INPUT ;
    USE SIGNAL ;
    SHAPE ABUTMENT ;
    PORT
      LAYER metal2 ;
      RECT 20.865 153.790 20.935 154.000 ;
    END
  END rw0_wmask_in[144]
  PIN rw0_wmask_in[145]
    DIRECTION INPUT ;
    USE SIGNAL ;
    SHAPE ABUTMENT ;
    PORT
      LAYER metal2 ;
      RECT 21.245 153.790 21.315 154.000 ;
    END
  END rw0_wmask_in[145]
  PIN rw0_wmask_in[146]
    DIRECTION INPUT ;
    USE SIGNAL ;
    SHAPE ABUTMENT ;
    PORT
      LAYER metal2 ;
      RECT 21.625 153.790 21.695 154.000 ;
    END
  END rw0_wmask_in[146]
  PIN rw0_wmask_in[147]
    DIRECTION INPUT ;
    USE SIGNAL ;
    SHAPE ABUTMENT ;
    PORT
      LAYER metal2 ;
      RECT 22.005 153.790 22.075 154.000 ;
    END
  END rw0_wmask_in[147]
  PIN rw0_wmask_in[148]
    DIRECTION INPUT ;
    USE SIGNAL ;
    SHAPE ABUTMENT ;
    PORT
      LAYER metal2 ;
      RECT 22.385 153.790 22.455 154.000 ;
    END
  END rw0_wmask_in[148]
  PIN rw0_wmask_in[149]
    DIRECTION INPUT ;
    USE SIGNAL ;
    SHAPE ABUTMENT ;
    PORT
      LAYER metal2 ;
      RECT 22.765 153.790 22.835 154.000 ;
    END
  END rw0_wmask_in[149]
  PIN rw0_wmask_in[150]
    DIRECTION INPUT ;
    USE SIGNAL ;
    SHAPE ABUTMENT ;
    PORT
      LAYER metal2 ;
      RECT 23.145 153.790 23.215 154.000 ;
    END
  END rw0_wmask_in[150]
  PIN rw0_wmask_in[151]
    DIRECTION INPUT ;
    USE SIGNAL ;
    SHAPE ABUTMENT ;
    PORT
      LAYER metal2 ;
      RECT 23.525 153.790 23.595 154.000 ;
    END
  END rw0_wmask_in[151]
  PIN rw0_wmask_in[152]
    DIRECTION INPUT ;
    USE SIGNAL ;
    SHAPE ABUTMENT ;
    PORT
      LAYER metal2 ;
      RECT 23.905 153.790 23.975 154.000 ;
    END
  END rw0_wmask_in[152]
  PIN rw0_wmask_in[153]
    DIRECTION INPUT ;
    USE SIGNAL ;
    SHAPE ABUTMENT ;
    PORT
      LAYER metal2 ;
      RECT 24.285 153.790 24.355 154.000 ;
    END
  END rw0_wmask_in[153]
  PIN rw0_wmask_in[154]
    DIRECTION INPUT ;
    USE SIGNAL ;
    SHAPE ABUTMENT ;
    PORT
      LAYER metal2 ;
      RECT 24.665 153.790 24.735 154.000 ;
    END
  END rw0_wmask_in[154]
  PIN rw0_wmask_in[155]
    DIRECTION INPUT ;
    USE SIGNAL ;
    SHAPE ABUTMENT ;
    PORT
      LAYER metal2 ;
      RECT 25.045 153.790 25.115 154.000 ;
    END
  END rw0_wmask_in[155]
  PIN rw0_wmask_in[156]
    DIRECTION INPUT ;
    USE SIGNAL ;
    SHAPE ABUTMENT ;
    PORT
      LAYER metal2 ;
      RECT 25.425 153.790 25.495 154.000 ;
    END
  END rw0_wmask_in[156]
  PIN rw0_wmask_in[157]
    DIRECTION INPUT ;
    USE SIGNAL ;
    SHAPE ABUTMENT ;
    PORT
      LAYER metal2 ;
      RECT 25.805 153.790 25.875 154.000 ;
    END
  END rw0_wmask_in[157]
  PIN rw0_wmask_in[158]
    DIRECTION INPUT ;
    USE SIGNAL ;
    SHAPE ABUTMENT ;
    PORT
      LAYER metal2 ;
      RECT 26.185 153.790 26.255 154.000 ;
    END
  END rw0_wmask_in[158]
  PIN rw0_wmask_in[159]
    DIRECTION INPUT ;
    USE SIGNAL ;
    SHAPE ABUTMENT ;
    PORT
      LAYER metal2 ;
      RECT 26.565 153.790 26.635 154.000 ;
    END
  END rw0_wmask_in[159]
  PIN rw0_wmask_in[160]
    DIRECTION INPUT ;
    USE SIGNAL ;
    SHAPE ABUTMENT ;
    PORT
      LAYER metal2 ;
      RECT 26.945 153.790 27.015 154.000 ;
    END
  END rw0_wmask_in[160]
  PIN rw0_wmask_in[161]
    DIRECTION INPUT ;
    USE SIGNAL ;
    SHAPE ABUTMENT ;
    PORT
      LAYER metal2 ;
      RECT 27.325 153.790 27.395 154.000 ;
    END
  END rw0_wmask_in[161]
  PIN rw0_wmask_in[162]
    DIRECTION INPUT ;
    USE SIGNAL ;
    SHAPE ABUTMENT ;
    PORT
      LAYER metal2 ;
      RECT 27.705 153.790 27.775 154.000 ;
    END
  END rw0_wmask_in[162]
  PIN rw0_wmask_in[163]
    DIRECTION INPUT ;
    USE SIGNAL ;
    SHAPE ABUTMENT ;
    PORT
      LAYER metal2 ;
      RECT 28.085 153.790 28.155 154.000 ;
    END
  END rw0_wmask_in[163]
  PIN rw0_wmask_in[164]
    DIRECTION INPUT ;
    USE SIGNAL ;
    SHAPE ABUTMENT ;
    PORT
      LAYER metal2 ;
      RECT 28.465 153.790 28.535 154.000 ;
    END
  END rw0_wmask_in[164]
  PIN rw0_wmask_in[165]
    DIRECTION INPUT ;
    USE SIGNAL ;
    SHAPE ABUTMENT ;
    PORT
      LAYER metal2 ;
      RECT 28.845 153.790 28.915 154.000 ;
    END
  END rw0_wmask_in[165]
  PIN rw0_wmask_in[166]
    DIRECTION INPUT ;
    USE SIGNAL ;
    SHAPE ABUTMENT ;
    PORT
      LAYER metal2 ;
      RECT 29.225 153.790 29.295 154.000 ;
    END
  END rw0_wmask_in[166]
  PIN rw0_wmask_in[167]
    DIRECTION INPUT ;
    USE SIGNAL ;
    SHAPE ABUTMENT ;
    PORT
      LAYER metal2 ;
      RECT 29.605 153.790 29.675 154.000 ;
    END
  END rw0_wmask_in[167]
  PIN rw0_wmask_in[168]
    DIRECTION INPUT ;
    USE SIGNAL ;
    SHAPE ABUTMENT ;
    PORT
      LAYER metal2 ;
      RECT 29.985 153.790 30.055 154.000 ;
    END
  END rw0_wmask_in[168]
  PIN rw0_wmask_in[169]
    DIRECTION INPUT ;
    USE SIGNAL ;
    SHAPE ABUTMENT ;
    PORT
      LAYER metal2 ;
      RECT 30.365 153.790 30.435 154.000 ;
    END
  END rw0_wmask_in[169]
  PIN rw0_wmask_in[170]
    DIRECTION INPUT ;
    USE SIGNAL ;
    SHAPE ABUTMENT ;
    PORT
      LAYER metal2 ;
      RECT 30.745 153.790 30.815 154.000 ;
    END
  END rw0_wmask_in[170]
  PIN rw0_wmask_in[171]
    DIRECTION INPUT ;
    USE SIGNAL ;
    SHAPE ABUTMENT ;
    PORT
      LAYER metal2 ;
      RECT 31.125 153.790 31.195 154.000 ;
    END
  END rw0_wmask_in[171]
  PIN rw0_wmask_in[172]
    DIRECTION INPUT ;
    USE SIGNAL ;
    SHAPE ABUTMENT ;
    PORT
      LAYER metal2 ;
      RECT 31.505 153.790 31.575 154.000 ;
    END
  END rw0_wmask_in[172]
  PIN rw0_wmask_in[173]
    DIRECTION INPUT ;
    USE SIGNAL ;
    SHAPE ABUTMENT ;
    PORT
      LAYER metal2 ;
      RECT 31.885 153.790 31.955 154.000 ;
    END
  END rw0_wmask_in[173]
  PIN rw0_wmask_in[174]
    DIRECTION INPUT ;
    USE SIGNAL ;
    SHAPE ABUTMENT ;
    PORT
      LAYER metal2 ;
      RECT 32.265 153.790 32.335 154.000 ;
    END
  END rw0_wmask_in[174]
  PIN rw0_wmask_in[175]
    DIRECTION INPUT ;
    USE SIGNAL ;
    SHAPE ABUTMENT ;
    PORT
      LAYER metal2 ;
      RECT 32.645 153.790 32.715 154.000 ;
    END
  END rw0_wmask_in[175]
  PIN rw0_wmask_in[176]
    DIRECTION INPUT ;
    USE SIGNAL ;
    SHAPE ABUTMENT ;
    PORT
      LAYER metal2 ;
      RECT 33.025 153.790 33.095 154.000 ;
    END
  END rw0_wmask_in[176]
  PIN rw0_wmask_in[177]
    DIRECTION INPUT ;
    USE SIGNAL ;
    SHAPE ABUTMENT ;
    PORT
      LAYER metal2 ;
      RECT 33.405 153.790 33.475 154.000 ;
    END
  END rw0_wmask_in[177]
  PIN rw0_wmask_in[178]
    DIRECTION INPUT ;
    USE SIGNAL ;
    SHAPE ABUTMENT ;
    PORT
      LAYER metal2 ;
      RECT 33.785 153.790 33.855 154.000 ;
    END
  END rw0_wmask_in[178]
  PIN rw0_wmask_in[179]
    DIRECTION INPUT ;
    USE SIGNAL ;
    SHAPE ABUTMENT ;
    PORT
      LAYER metal2 ;
      RECT 34.165 153.790 34.235 154.000 ;
    END
  END rw0_wmask_in[179]
  PIN rw0_wmask_in[180]
    DIRECTION INPUT ;
    USE SIGNAL ;
    SHAPE ABUTMENT ;
    PORT
      LAYER metal2 ;
      RECT 34.545 153.790 34.615 154.000 ;
    END
  END rw0_wmask_in[180]
  PIN rw0_wmask_in[181]
    DIRECTION INPUT ;
    USE SIGNAL ;
    SHAPE ABUTMENT ;
    PORT
      LAYER metal2 ;
      RECT 34.925 153.790 34.995 154.000 ;
    END
  END rw0_wmask_in[181]
  PIN rw0_wmask_in[182]
    DIRECTION INPUT ;
    USE SIGNAL ;
    SHAPE ABUTMENT ;
    PORT
      LAYER metal2 ;
      RECT 35.305 153.790 35.375 154.000 ;
    END
  END rw0_wmask_in[182]
  PIN rw0_wmask_in[183]
    DIRECTION INPUT ;
    USE SIGNAL ;
    SHAPE ABUTMENT ;
    PORT
      LAYER metal2 ;
      RECT 35.685 153.790 35.755 154.000 ;
    END
  END rw0_wmask_in[183]
  PIN rw0_wd_in[0]
    DIRECTION INPUT ;
    USE SIGNAL ;
    SHAPE ABUTMENT ;
    PORT
      LAYER metal3 ;
      RECT 0.000 71.645 0.210 71.715 ;
    END
  END rw0_wd_in[0]
  PIN rw0_wd_in[1]
    DIRECTION INPUT ;
    USE SIGNAL ;
    SHAPE ABUTMENT ;
    PORT
      LAYER metal3 ;
      RECT 0.000 73.185 0.210 73.255 ;
    END
  END rw0_wd_in[1]
  PIN rw0_wd_in[2]
    DIRECTION INPUT ;
    USE SIGNAL ;
    SHAPE ABUTMENT ;
    PORT
      LAYER metal3 ;
      RECT 0.000 74.725 0.210 74.795 ;
    END
  END rw0_wd_in[2]
  PIN rw0_wd_in[3]
    DIRECTION INPUT ;
    USE SIGNAL ;
    SHAPE ABUTMENT ;
    PORT
      LAYER metal3 ;
      RECT 0.000 76.265 0.210 76.335 ;
    END
  END rw0_wd_in[3]
  PIN rw0_wd_in[4]
    DIRECTION INPUT ;
    USE SIGNAL ;
    SHAPE ABUTMENT ;
    PORT
      LAYER metal3 ;
      RECT 0.000 77.805 0.210 77.875 ;
    END
  END rw0_wd_in[4]
  PIN rw0_wd_in[5]
    DIRECTION INPUT ;
    USE SIGNAL ;
    SHAPE ABUTMENT ;
    PORT
      LAYER metal3 ;
      RECT 0.000 79.345 0.210 79.415 ;
    END
  END rw0_wd_in[5]
  PIN rw0_wd_in[6]
    DIRECTION INPUT ;
    USE SIGNAL ;
    SHAPE ABUTMENT ;
    PORT
      LAYER metal3 ;
      RECT 0.000 80.885 0.210 80.955 ;
    END
  END rw0_wd_in[6]
  PIN rw0_wd_in[7]
    DIRECTION INPUT ;
    USE SIGNAL ;
    SHAPE ABUTMENT ;
    PORT
      LAYER metal3 ;
      RECT 0.000 82.425 0.210 82.495 ;
    END
  END rw0_wd_in[7]
  PIN rw0_wd_in[8]
    DIRECTION INPUT ;
    USE SIGNAL ;
    SHAPE ABUTMENT ;
    PORT
      LAYER metal3 ;
      RECT 0.000 83.965 0.210 84.035 ;
    END
  END rw0_wd_in[8]
  PIN rw0_wd_in[9]
    DIRECTION INPUT ;
    USE SIGNAL ;
    SHAPE ABUTMENT ;
    PORT
      LAYER metal3 ;
      RECT 0.000 85.505 0.210 85.575 ;
    END
  END rw0_wd_in[9]
  PIN rw0_wd_in[10]
    DIRECTION INPUT ;
    USE SIGNAL ;
    SHAPE ABUTMENT ;
    PORT
      LAYER metal3 ;
      RECT 0.000 87.045 0.210 87.115 ;
    END
  END rw0_wd_in[10]
  PIN rw0_wd_in[11]
    DIRECTION INPUT ;
    USE SIGNAL ;
    SHAPE ABUTMENT ;
    PORT
      LAYER metal3 ;
      RECT 0.000 88.585 0.210 88.655 ;
    END
  END rw0_wd_in[11]
  PIN rw0_wd_in[12]
    DIRECTION INPUT ;
    USE SIGNAL ;
    SHAPE ABUTMENT ;
    PORT
      LAYER metal3 ;
      RECT 0.000 90.125 0.210 90.195 ;
    END
  END rw0_wd_in[12]
  PIN rw0_wd_in[13]
    DIRECTION INPUT ;
    USE SIGNAL ;
    SHAPE ABUTMENT ;
    PORT
      LAYER metal3 ;
      RECT 0.000 91.665 0.210 91.735 ;
    END
  END rw0_wd_in[13]
  PIN rw0_wd_in[14]
    DIRECTION INPUT ;
    USE SIGNAL ;
    SHAPE ABUTMENT ;
    PORT
      LAYER metal3 ;
      RECT 0.000 93.205 0.210 93.275 ;
    END
  END rw0_wd_in[14]
  PIN rw0_wd_in[15]
    DIRECTION INPUT ;
    USE SIGNAL ;
    SHAPE ABUTMENT ;
    PORT
      LAYER metal3 ;
      RECT 0.000 94.745 0.210 94.815 ;
    END
  END rw0_wd_in[15]
  PIN rw0_wd_in[16]
    DIRECTION INPUT ;
    USE SIGNAL ;
    SHAPE ABUTMENT ;
    PORT
      LAYER metal3 ;
      RECT 0.000 96.285 0.210 96.355 ;
    END
  END rw0_wd_in[16]
  PIN rw0_wd_in[17]
    DIRECTION INPUT ;
    USE SIGNAL ;
    SHAPE ABUTMENT ;
    PORT
      LAYER metal3 ;
      RECT 0.000 97.825 0.210 97.895 ;
    END
  END rw0_wd_in[17]
  PIN rw0_wd_in[18]
    DIRECTION INPUT ;
    USE SIGNAL ;
    SHAPE ABUTMENT ;
    PORT
      LAYER metal3 ;
      RECT 0.000 99.365 0.210 99.435 ;
    END
  END rw0_wd_in[18]
  PIN rw0_wd_in[19]
    DIRECTION INPUT ;
    USE SIGNAL ;
    SHAPE ABUTMENT ;
    PORT
      LAYER metal3 ;
      RECT 0.000 100.905 0.210 100.975 ;
    END
  END rw0_wd_in[19]
  PIN rw0_wd_in[20]
    DIRECTION INPUT ;
    USE SIGNAL ;
    SHAPE ABUTMENT ;
    PORT
      LAYER metal3 ;
      RECT 0.000 102.445 0.210 102.515 ;
    END
  END rw0_wd_in[20]
  PIN rw0_wd_in[21]
    DIRECTION INPUT ;
    USE SIGNAL ;
    SHAPE ABUTMENT ;
    PORT
      LAYER metal3 ;
      RECT 0.000 103.985 0.210 104.055 ;
    END
  END rw0_wd_in[21]
  PIN rw0_wd_in[22]
    DIRECTION INPUT ;
    USE SIGNAL ;
    SHAPE ABUTMENT ;
    PORT
      LAYER metal3 ;
      RECT 0.000 105.525 0.210 105.595 ;
    END
  END rw0_wd_in[22]
  PIN rw0_wd_in[23]
    DIRECTION INPUT ;
    USE SIGNAL ;
    SHAPE ABUTMENT ;
    PORT
      LAYER metal3 ;
      RECT 0.000 107.065 0.210 107.135 ;
    END
  END rw0_wd_in[23]
  PIN rw0_wd_in[24]
    DIRECTION INPUT ;
    USE SIGNAL ;
    SHAPE ABUTMENT ;
    PORT
      LAYER metal3 ;
      RECT 0.000 108.605 0.210 108.675 ;
    END
  END rw0_wd_in[24]
  PIN rw0_wd_in[25]
    DIRECTION INPUT ;
    USE SIGNAL ;
    SHAPE ABUTMENT ;
    PORT
      LAYER metal3 ;
      RECT 0.000 110.145 0.210 110.215 ;
    END
  END rw0_wd_in[25]
  PIN rw0_wd_in[26]
    DIRECTION INPUT ;
    USE SIGNAL ;
    SHAPE ABUTMENT ;
    PORT
      LAYER metal3 ;
      RECT 0.000 111.685 0.210 111.755 ;
    END
  END rw0_wd_in[26]
  PIN rw0_wd_in[27]
    DIRECTION INPUT ;
    USE SIGNAL ;
    SHAPE ABUTMENT ;
    PORT
      LAYER metal3 ;
      RECT 0.000 113.225 0.210 113.295 ;
    END
  END rw0_wd_in[27]
  PIN rw0_wd_in[28]
    DIRECTION INPUT ;
    USE SIGNAL ;
    SHAPE ABUTMENT ;
    PORT
      LAYER metal3 ;
      RECT 0.000 114.765 0.210 114.835 ;
    END
  END rw0_wd_in[28]
  PIN rw0_wd_in[29]
    DIRECTION INPUT ;
    USE SIGNAL ;
    SHAPE ABUTMENT ;
    PORT
      LAYER metal3 ;
      RECT 0.000 116.305 0.210 116.375 ;
    END
  END rw0_wd_in[29]
  PIN rw0_wd_in[30]
    DIRECTION INPUT ;
    USE SIGNAL ;
    SHAPE ABUTMENT ;
    PORT
      LAYER metal3 ;
      RECT 0.000 117.845 0.210 117.915 ;
    END
  END rw0_wd_in[30]
  PIN rw0_wd_in[31]
    DIRECTION INPUT ;
    USE SIGNAL ;
    SHAPE ABUTMENT ;
    PORT
      LAYER metal3 ;
      RECT 0.000 119.385 0.210 119.455 ;
    END
  END rw0_wd_in[31]
  PIN rw0_wd_in[32]
    DIRECTION INPUT ;
    USE SIGNAL ;
    SHAPE ABUTMENT ;
    PORT
      LAYER metal3 ;
      RECT 0.000 120.925 0.210 120.995 ;
    END
  END rw0_wd_in[32]
  PIN rw0_wd_in[33]
    DIRECTION INPUT ;
    USE SIGNAL ;
    SHAPE ABUTMENT ;
    PORT
      LAYER metal3 ;
      RECT 0.000 122.465 0.210 122.535 ;
    END
  END rw0_wd_in[33]
  PIN rw0_wd_in[34]
    DIRECTION INPUT ;
    USE SIGNAL ;
    SHAPE ABUTMENT ;
    PORT
      LAYER metal3 ;
      RECT 0.000 124.005 0.210 124.075 ;
    END
  END rw0_wd_in[34]
  PIN rw0_wd_in[35]
    DIRECTION INPUT ;
    USE SIGNAL ;
    SHAPE ABUTMENT ;
    PORT
      LAYER metal3 ;
      RECT 0.000 125.545 0.210 125.615 ;
    END
  END rw0_wd_in[35]
  PIN rw0_wd_in[36]
    DIRECTION INPUT ;
    USE SIGNAL ;
    SHAPE ABUTMENT ;
    PORT
      LAYER metal3 ;
      RECT 0.000 127.085 0.210 127.155 ;
    END
  END rw0_wd_in[36]
  PIN rw0_wd_in[37]
    DIRECTION INPUT ;
    USE SIGNAL ;
    SHAPE ABUTMENT ;
    PORT
      LAYER metal3 ;
      RECT 0.000 128.625 0.210 128.695 ;
    END
  END rw0_wd_in[37]
  PIN rw0_wd_in[38]
    DIRECTION INPUT ;
    USE SIGNAL ;
    SHAPE ABUTMENT ;
    PORT
      LAYER metal3 ;
      RECT 0.000 130.165 0.210 130.235 ;
    END
  END rw0_wd_in[38]
  PIN rw0_wd_in[39]
    DIRECTION INPUT ;
    USE SIGNAL ;
    SHAPE ABUTMENT ;
    PORT
      LAYER metal3 ;
      RECT 0.000 131.705 0.210 131.775 ;
    END
  END rw0_wd_in[39]
  PIN rw0_wd_in[40]
    DIRECTION INPUT ;
    USE SIGNAL ;
    SHAPE ABUTMENT ;
    PORT
      LAYER metal3 ;
      RECT 0.000 133.245 0.210 133.315 ;
    END
  END rw0_wd_in[40]
  PIN rw0_wd_in[41]
    DIRECTION INPUT ;
    USE SIGNAL ;
    SHAPE ABUTMENT ;
    PORT
      LAYER metal3 ;
      RECT 0.000 134.785 0.210 134.855 ;
    END
  END rw0_wd_in[41]
  PIN rw0_wd_in[42]
    DIRECTION INPUT ;
    USE SIGNAL ;
    SHAPE ABUTMENT ;
    PORT
      LAYER metal3 ;
      RECT 0.000 136.325 0.210 136.395 ;
    END
  END rw0_wd_in[42]
  PIN rw0_wd_in[43]
    DIRECTION INPUT ;
    USE SIGNAL ;
    SHAPE ABUTMENT ;
    PORT
      LAYER metal3 ;
      RECT 0.000 137.865 0.210 137.935 ;
    END
  END rw0_wd_in[43]
  PIN rw0_wd_in[44]
    DIRECTION INPUT ;
    USE SIGNAL ;
    SHAPE ABUTMENT ;
    PORT
      LAYER metal3 ;
      RECT 0.000 139.405 0.210 139.475 ;
    END
  END rw0_wd_in[44]
  PIN rw0_wd_in[45]
    DIRECTION INPUT ;
    USE SIGNAL ;
    SHAPE ABUTMENT ;
    PORT
      LAYER metal3 ;
      RECT 0.000 140.945 0.210 141.015 ;
    END
  END rw0_wd_in[45]
  PIN rw0_wd_in[46]
    DIRECTION INPUT ;
    USE SIGNAL ;
    SHAPE ABUTMENT ;
    PORT
      LAYER metal3 ;
      RECT 92.700 71.645 92.910 71.715 ;
    END
  END rw0_wd_in[46]
  PIN rw0_wd_in[47]
    DIRECTION INPUT ;
    USE SIGNAL ;
    SHAPE ABUTMENT ;
    PORT
      LAYER metal3 ;
      RECT 92.700 73.185 92.910 73.255 ;
    END
  END rw0_wd_in[47]
  PIN rw0_wd_in[48]
    DIRECTION INPUT ;
    USE SIGNAL ;
    SHAPE ABUTMENT ;
    PORT
      LAYER metal3 ;
      RECT 92.700 74.725 92.910 74.795 ;
    END
  END rw0_wd_in[48]
  PIN rw0_wd_in[49]
    DIRECTION INPUT ;
    USE SIGNAL ;
    SHAPE ABUTMENT ;
    PORT
      LAYER metal3 ;
      RECT 92.700 76.265 92.910 76.335 ;
    END
  END rw0_wd_in[49]
  PIN rw0_wd_in[50]
    DIRECTION INPUT ;
    USE SIGNAL ;
    SHAPE ABUTMENT ;
    PORT
      LAYER metal3 ;
      RECT 92.700 77.805 92.910 77.875 ;
    END
  END rw0_wd_in[50]
  PIN rw0_wd_in[51]
    DIRECTION INPUT ;
    USE SIGNAL ;
    SHAPE ABUTMENT ;
    PORT
      LAYER metal3 ;
      RECT 92.700 79.345 92.910 79.415 ;
    END
  END rw0_wd_in[51]
  PIN rw0_wd_in[52]
    DIRECTION INPUT ;
    USE SIGNAL ;
    SHAPE ABUTMENT ;
    PORT
      LAYER metal3 ;
      RECT 92.700 80.885 92.910 80.955 ;
    END
  END rw0_wd_in[52]
  PIN rw0_wd_in[53]
    DIRECTION INPUT ;
    USE SIGNAL ;
    SHAPE ABUTMENT ;
    PORT
      LAYER metal3 ;
      RECT 92.700 82.425 92.910 82.495 ;
    END
  END rw0_wd_in[53]
  PIN rw0_wd_in[54]
    DIRECTION INPUT ;
    USE SIGNAL ;
    SHAPE ABUTMENT ;
    PORT
      LAYER metal3 ;
      RECT 92.700 83.965 92.910 84.035 ;
    END
  END rw0_wd_in[54]
  PIN rw0_wd_in[55]
    DIRECTION INPUT ;
    USE SIGNAL ;
    SHAPE ABUTMENT ;
    PORT
      LAYER metal3 ;
      RECT 92.700 85.505 92.910 85.575 ;
    END
  END rw0_wd_in[55]
  PIN rw0_wd_in[56]
    DIRECTION INPUT ;
    USE SIGNAL ;
    SHAPE ABUTMENT ;
    PORT
      LAYER metal3 ;
      RECT 92.700 87.045 92.910 87.115 ;
    END
  END rw0_wd_in[56]
  PIN rw0_wd_in[57]
    DIRECTION INPUT ;
    USE SIGNAL ;
    SHAPE ABUTMENT ;
    PORT
      LAYER metal3 ;
      RECT 92.700 88.585 92.910 88.655 ;
    END
  END rw0_wd_in[57]
  PIN rw0_wd_in[58]
    DIRECTION INPUT ;
    USE SIGNAL ;
    SHAPE ABUTMENT ;
    PORT
      LAYER metal3 ;
      RECT 92.700 90.125 92.910 90.195 ;
    END
  END rw0_wd_in[58]
  PIN rw0_wd_in[59]
    DIRECTION INPUT ;
    USE SIGNAL ;
    SHAPE ABUTMENT ;
    PORT
      LAYER metal3 ;
      RECT 92.700 91.665 92.910 91.735 ;
    END
  END rw0_wd_in[59]
  PIN rw0_wd_in[60]
    DIRECTION INPUT ;
    USE SIGNAL ;
    SHAPE ABUTMENT ;
    PORT
      LAYER metal3 ;
      RECT 92.700 93.205 92.910 93.275 ;
    END
  END rw0_wd_in[60]
  PIN rw0_wd_in[61]
    DIRECTION INPUT ;
    USE SIGNAL ;
    SHAPE ABUTMENT ;
    PORT
      LAYER metal3 ;
      RECT 92.700 94.745 92.910 94.815 ;
    END
  END rw0_wd_in[61]
  PIN rw0_wd_in[62]
    DIRECTION INPUT ;
    USE SIGNAL ;
    SHAPE ABUTMENT ;
    PORT
      LAYER metal3 ;
      RECT 92.700 96.285 92.910 96.355 ;
    END
  END rw0_wd_in[62]
  PIN rw0_wd_in[63]
    DIRECTION INPUT ;
    USE SIGNAL ;
    SHAPE ABUTMENT ;
    PORT
      LAYER metal3 ;
      RECT 92.700 97.825 92.910 97.895 ;
    END
  END rw0_wd_in[63]
  PIN rw0_wd_in[64]
    DIRECTION INPUT ;
    USE SIGNAL ;
    SHAPE ABUTMENT ;
    PORT
      LAYER metal3 ;
      RECT 92.700 99.365 92.910 99.435 ;
    END
  END rw0_wd_in[64]
  PIN rw0_wd_in[65]
    DIRECTION INPUT ;
    USE SIGNAL ;
    SHAPE ABUTMENT ;
    PORT
      LAYER metal3 ;
      RECT 92.700 100.905 92.910 100.975 ;
    END
  END rw0_wd_in[65]
  PIN rw0_wd_in[66]
    DIRECTION INPUT ;
    USE SIGNAL ;
    SHAPE ABUTMENT ;
    PORT
      LAYER metal3 ;
      RECT 92.700 102.445 92.910 102.515 ;
    END
  END rw0_wd_in[66]
  PIN rw0_wd_in[67]
    DIRECTION INPUT ;
    USE SIGNAL ;
    SHAPE ABUTMENT ;
    PORT
      LAYER metal3 ;
      RECT 92.700 103.985 92.910 104.055 ;
    END
  END rw0_wd_in[67]
  PIN rw0_wd_in[68]
    DIRECTION INPUT ;
    USE SIGNAL ;
    SHAPE ABUTMENT ;
    PORT
      LAYER metal3 ;
      RECT 92.700 105.525 92.910 105.595 ;
    END
  END rw0_wd_in[68]
  PIN rw0_wd_in[69]
    DIRECTION INPUT ;
    USE SIGNAL ;
    SHAPE ABUTMENT ;
    PORT
      LAYER metal3 ;
      RECT 92.700 107.065 92.910 107.135 ;
    END
  END rw0_wd_in[69]
  PIN rw0_wd_in[70]
    DIRECTION INPUT ;
    USE SIGNAL ;
    SHAPE ABUTMENT ;
    PORT
      LAYER metal3 ;
      RECT 92.700 108.605 92.910 108.675 ;
    END
  END rw0_wd_in[70]
  PIN rw0_wd_in[71]
    DIRECTION INPUT ;
    USE SIGNAL ;
    SHAPE ABUTMENT ;
    PORT
      LAYER metal3 ;
      RECT 92.700 110.145 92.910 110.215 ;
    END
  END rw0_wd_in[71]
  PIN rw0_wd_in[72]
    DIRECTION INPUT ;
    USE SIGNAL ;
    SHAPE ABUTMENT ;
    PORT
      LAYER metal3 ;
      RECT 92.700 111.685 92.910 111.755 ;
    END
  END rw0_wd_in[72]
  PIN rw0_wd_in[73]
    DIRECTION INPUT ;
    USE SIGNAL ;
    SHAPE ABUTMENT ;
    PORT
      LAYER metal3 ;
      RECT 92.700 113.225 92.910 113.295 ;
    END
  END rw0_wd_in[73]
  PIN rw0_wd_in[74]
    DIRECTION INPUT ;
    USE SIGNAL ;
    SHAPE ABUTMENT ;
    PORT
      LAYER metal3 ;
      RECT 92.700 114.765 92.910 114.835 ;
    END
  END rw0_wd_in[74]
  PIN rw0_wd_in[75]
    DIRECTION INPUT ;
    USE SIGNAL ;
    SHAPE ABUTMENT ;
    PORT
      LAYER metal3 ;
      RECT 92.700 116.305 92.910 116.375 ;
    END
  END rw0_wd_in[75]
  PIN rw0_wd_in[76]
    DIRECTION INPUT ;
    USE SIGNAL ;
    SHAPE ABUTMENT ;
    PORT
      LAYER metal3 ;
      RECT 92.700 117.845 92.910 117.915 ;
    END
  END rw0_wd_in[76]
  PIN rw0_wd_in[77]
    DIRECTION INPUT ;
    USE SIGNAL ;
    SHAPE ABUTMENT ;
    PORT
      LAYER metal3 ;
      RECT 92.700 119.385 92.910 119.455 ;
    END
  END rw0_wd_in[77]
  PIN rw0_wd_in[78]
    DIRECTION INPUT ;
    USE SIGNAL ;
    SHAPE ABUTMENT ;
    PORT
      LAYER metal3 ;
      RECT 92.700 120.925 92.910 120.995 ;
    END
  END rw0_wd_in[78]
  PIN rw0_wd_in[79]
    DIRECTION INPUT ;
    USE SIGNAL ;
    SHAPE ABUTMENT ;
    PORT
      LAYER metal3 ;
      RECT 92.700 122.465 92.910 122.535 ;
    END
  END rw0_wd_in[79]
  PIN rw0_wd_in[80]
    DIRECTION INPUT ;
    USE SIGNAL ;
    SHAPE ABUTMENT ;
    PORT
      LAYER metal3 ;
      RECT 92.700 124.005 92.910 124.075 ;
    END
  END rw0_wd_in[80]
  PIN rw0_wd_in[81]
    DIRECTION INPUT ;
    USE SIGNAL ;
    SHAPE ABUTMENT ;
    PORT
      LAYER metal3 ;
      RECT 92.700 125.545 92.910 125.615 ;
    END
  END rw0_wd_in[81]
  PIN rw0_wd_in[82]
    DIRECTION INPUT ;
    USE SIGNAL ;
    SHAPE ABUTMENT ;
    PORT
      LAYER metal3 ;
      RECT 92.700 127.085 92.910 127.155 ;
    END
  END rw0_wd_in[82]
  PIN rw0_wd_in[83]
    DIRECTION INPUT ;
    USE SIGNAL ;
    SHAPE ABUTMENT ;
    PORT
      LAYER metal3 ;
      RECT 92.700 128.625 92.910 128.695 ;
    END
  END rw0_wd_in[83]
  PIN rw0_wd_in[84]
    DIRECTION INPUT ;
    USE SIGNAL ;
    SHAPE ABUTMENT ;
    PORT
      LAYER metal3 ;
      RECT 92.700 130.165 92.910 130.235 ;
    END
  END rw0_wd_in[84]
  PIN rw0_wd_in[85]
    DIRECTION INPUT ;
    USE SIGNAL ;
    SHAPE ABUTMENT ;
    PORT
      LAYER metal3 ;
      RECT 92.700 131.705 92.910 131.775 ;
    END
  END rw0_wd_in[85]
  PIN rw0_wd_in[86]
    DIRECTION INPUT ;
    USE SIGNAL ;
    SHAPE ABUTMENT ;
    PORT
      LAYER metal3 ;
      RECT 92.700 133.245 92.910 133.315 ;
    END
  END rw0_wd_in[86]
  PIN rw0_wd_in[87]
    DIRECTION INPUT ;
    USE SIGNAL ;
    SHAPE ABUTMENT ;
    PORT
      LAYER metal3 ;
      RECT 92.700 134.785 92.910 134.855 ;
    END
  END rw0_wd_in[87]
  PIN rw0_wd_in[88]
    DIRECTION INPUT ;
    USE SIGNAL ;
    SHAPE ABUTMENT ;
    PORT
      LAYER metal3 ;
      RECT 92.700 136.325 92.910 136.395 ;
    END
  END rw0_wd_in[88]
  PIN rw0_wd_in[89]
    DIRECTION INPUT ;
    USE SIGNAL ;
    SHAPE ABUTMENT ;
    PORT
      LAYER metal3 ;
      RECT 92.700 137.865 92.910 137.935 ;
    END
  END rw0_wd_in[89]
  PIN rw0_wd_in[90]
    DIRECTION INPUT ;
    USE SIGNAL ;
    SHAPE ABUTMENT ;
    PORT
      LAYER metal3 ;
      RECT 92.700 139.405 92.910 139.475 ;
    END
  END rw0_wd_in[90]
  PIN rw0_wd_in[91]
    DIRECTION INPUT ;
    USE SIGNAL ;
    SHAPE ABUTMENT ;
    PORT
      LAYER metal3 ;
      RECT 92.700 140.945 92.910 141.015 ;
    END
  END rw0_wd_in[91]
  PIN rw0_wd_in[92]
    DIRECTION INPUT ;
    USE SIGNAL ;
    SHAPE ABUTMENT ;
    PORT
      LAYER metal2 ;
      RECT 1.105 0.000 1.175 0.210 ;
    END
  END rw0_wd_in[92]
  PIN rw0_wd_in[93]
    DIRECTION INPUT ;
    USE SIGNAL ;
    SHAPE ABUTMENT ;
    PORT
      LAYER metal2 ;
      RECT 1.485 0.000 1.555 0.210 ;
    END
  END rw0_wd_in[93]
  PIN rw0_wd_in[94]
    DIRECTION INPUT ;
    USE SIGNAL ;
    SHAPE ABUTMENT ;
    PORT
      LAYER metal2 ;
      RECT 1.865 0.000 1.935 0.210 ;
    END
  END rw0_wd_in[94]
  PIN rw0_wd_in[95]
    DIRECTION INPUT ;
    USE SIGNAL ;
    SHAPE ABUTMENT ;
    PORT
      LAYER metal2 ;
      RECT 2.245 0.000 2.315 0.210 ;
    END
  END rw0_wd_in[95]
  PIN rw0_wd_in[96]
    DIRECTION INPUT ;
    USE SIGNAL ;
    SHAPE ABUTMENT ;
    PORT
      LAYER metal2 ;
      RECT 2.625 0.000 2.695 0.210 ;
    END
  END rw0_wd_in[96]
  PIN rw0_wd_in[97]
    DIRECTION INPUT ;
    USE SIGNAL ;
    SHAPE ABUTMENT ;
    PORT
      LAYER metal2 ;
      RECT 3.005 0.000 3.075 0.210 ;
    END
  END rw0_wd_in[97]
  PIN rw0_wd_in[98]
    DIRECTION INPUT ;
    USE SIGNAL ;
    SHAPE ABUTMENT ;
    PORT
      LAYER metal2 ;
      RECT 3.385 0.000 3.455 0.210 ;
    END
  END rw0_wd_in[98]
  PIN rw0_wd_in[99]
    DIRECTION INPUT ;
    USE SIGNAL ;
    SHAPE ABUTMENT ;
    PORT
      LAYER metal2 ;
      RECT 3.765 0.000 3.835 0.210 ;
    END
  END rw0_wd_in[99]
  PIN rw0_wd_in[100]
    DIRECTION INPUT ;
    USE SIGNAL ;
    SHAPE ABUTMENT ;
    PORT
      LAYER metal2 ;
      RECT 4.145 0.000 4.215 0.210 ;
    END
  END rw0_wd_in[100]
  PIN rw0_wd_in[101]
    DIRECTION INPUT ;
    USE SIGNAL ;
    SHAPE ABUTMENT ;
    PORT
      LAYER metal2 ;
      RECT 4.525 0.000 4.595 0.210 ;
    END
  END rw0_wd_in[101]
  PIN rw0_wd_in[102]
    DIRECTION INPUT ;
    USE SIGNAL ;
    SHAPE ABUTMENT ;
    PORT
      LAYER metal2 ;
      RECT 4.905 0.000 4.975 0.210 ;
    END
  END rw0_wd_in[102]
  PIN rw0_wd_in[103]
    DIRECTION INPUT ;
    USE SIGNAL ;
    SHAPE ABUTMENT ;
    PORT
      LAYER metal2 ;
      RECT 5.285 0.000 5.355 0.210 ;
    END
  END rw0_wd_in[103]
  PIN rw0_wd_in[104]
    DIRECTION INPUT ;
    USE SIGNAL ;
    SHAPE ABUTMENT ;
    PORT
      LAYER metal2 ;
      RECT 5.665 0.000 5.735 0.210 ;
    END
  END rw0_wd_in[104]
  PIN rw0_wd_in[105]
    DIRECTION INPUT ;
    USE SIGNAL ;
    SHAPE ABUTMENT ;
    PORT
      LAYER metal2 ;
      RECT 6.045 0.000 6.115 0.210 ;
    END
  END rw0_wd_in[105]
  PIN rw0_wd_in[106]
    DIRECTION INPUT ;
    USE SIGNAL ;
    SHAPE ABUTMENT ;
    PORT
      LAYER metal2 ;
      RECT 6.425 0.000 6.495 0.210 ;
    END
  END rw0_wd_in[106]
  PIN rw0_wd_in[107]
    DIRECTION INPUT ;
    USE SIGNAL ;
    SHAPE ABUTMENT ;
    PORT
      LAYER metal2 ;
      RECT 6.805 0.000 6.875 0.210 ;
    END
  END rw0_wd_in[107]
  PIN rw0_wd_in[108]
    DIRECTION INPUT ;
    USE SIGNAL ;
    SHAPE ABUTMENT ;
    PORT
      LAYER metal2 ;
      RECT 7.185 0.000 7.255 0.210 ;
    END
  END rw0_wd_in[108]
  PIN rw0_wd_in[109]
    DIRECTION INPUT ;
    USE SIGNAL ;
    SHAPE ABUTMENT ;
    PORT
      LAYER metal2 ;
      RECT 7.565 0.000 7.635 0.210 ;
    END
  END rw0_wd_in[109]
  PIN rw0_wd_in[110]
    DIRECTION INPUT ;
    USE SIGNAL ;
    SHAPE ABUTMENT ;
    PORT
      LAYER metal2 ;
      RECT 7.945 0.000 8.015 0.210 ;
    END
  END rw0_wd_in[110]
  PIN rw0_wd_in[111]
    DIRECTION INPUT ;
    USE SIGNAL ;
    SHAPE ABUTMENT ;
    PORT
      LAYER metal2 ;
      RECT 8.325 0.000 8.395 0.210 ;
    END
  END rw0_wd_in[111]
  PIN rw0_wd_in[112]
    DIRECTION INPUT ;
    USE SIGNAL ;
    SHAPE ABUTMENT ;
    PORT
      LAYER metal2 ;
      RECT 8.705 0.000 8.775 0.210 ;
    END
  END rw0_wd_in[112]
  PIN rw0_wd_in[113]
    DIRECTION INPUT ;
    USE SIGNAL ;
    SHAPE ABUTMENT ;
    PORT
      LAYER metal2 ;
      RECT 9.085 0.000 9.155 0.210 ;
    END
  END rw0_wd_in[113]
  PIN rw0_wd_in[114]
    DIRECTION INPUT ;
    USE SIGNAL ;
    SHAPE ABUTMENT ;
    PORT
      LAYER metal2 ;
      RECT 9.465 0.000 9.535 0.210 ;
    END
  END rw0_wd_in[114]
  PIN rw0_wd_in[115]
    DIRECTION INPUT ;
    USE SIGNAL ;
    SHAPE ABUTMENT ;
    PORT
      LAYER metal2 ;
      RECT 9.845 0.000 9.915 0.210 ;
    END
  END rw0_wd_in[115]
  PIN rw0_wd_in[116]
    DIRECTION INPUT ;
    USE SIGNAL ;
    SHAPE ABUTMENT ;
    PORT
      LAYER metal2 ;
      RECT 10.225 0.000 10.295 0.210 ;
    END
  END rw0_wd_in[116]
  PIN rw0_wd_in[117]
    DIRECTION INPUT ;
    USE SIGNAL ;
    SHAPE ABUTMENT ;
    PORT
      LAYER metal2 ;
      RECT 10.605 0.000 10.675 0.210 ;
    END
  END rw0_wd_in[117]
  PIN rw0_wd_in[118]
    DIRECTION INPUT ;
    USE SIGNAL ;
    SHAPE ABUTMENT ;
    PORT
      LAYER metal2 ;
      RECT 10.985 0.000 11.055 0.210 ;
    END
  END rw0_wd_in[118]
  PIN rw0_wd_in[119]
    DIRECTION INPUT ;
    USE SIGNAL ;
    SHAPE ABUTMENT ;
    PORT
      LAYER metal2 ;
      RECT 11.365 0.000 11.435 0.210 ;
    END
  END rw0_wd_in[119]
  PIN rw0_wd_in[120]
    DIRECTION INPUT ;
    USE SIGNAL ;
    SHAPE ABUTMENT ;
    PORT
      LAYER metal2 ;
      RECT 11.745 0.000 11.815 0.210 ;
    END
  END rw0_wd_in[120]
  PIN rw0_wd_in[121]
    DIRECTION INPUT ;
    USE SIGNAL ;
    SHAPE ABUTMENT ;
    PORT
      LAYER metal2 ;
      RECT 12.125 0.000 12.195 0.210 ;
    END
  END rw0_wd_in[121]
  PIN rw0_wd_in[122]
    DIRECTION INPUT ;
    USE SIGNAL ;
    SHAPE ABUTMENT ;
    PORT
      LAYER metal2 ;
      RECT 12.505 0.000 12.575 0.210 ;
    END
  END rw0_wd_in[122]
  PIN rw0_wd_in[123]
    DIRECTION INPUT ;
    USE SIGNAL ;
    SHAPE ABUTMENT ;
    PORT
      LAYER metal2 ;
      RECT 12.885 0.000 12.955 0.210 ;
    END
  END rw0_wd_in[123]
  PIN rw0_wd_in[124]
    DIRECTION INPUT ;
    USE SIGNAL ;
    SHAPE ABUTMENT ;
    PORT
      LAYER metal2 ;
      RECT 13.265 0.000 13.335 0.210 ;
    END
  END rw0_wd_in[124]
  PIN rw0_wd_in[125]
    DIRECTION INPUT ;
    USE SIGNAL ;
    SHAPE ABUTMENT ;
    PORT
      LAYER metal2 ;
      RECT 13.645 0.000 13.715 0.210 ;
    END
  END rw0_wd_in[125]
  PIN rw0_wd_in[126]
    DIRECTION INPUT ;
    USE SIGNAL ;
    SHAPE ABUTMENT ;
    PORT
      LAYER metal2 ;
      RECT 14.025 0.000 14.095 0.210 ;
    END
  END rw0_wd_in[126]
  PIN rw0_wd_in[127]
    DIRECTION INPUT ;
    USE SIGNAL ;
    SHAPE ABUTMENT ;
    PORT
      LAYER metal2 ;
      RECT 14.405 0.000 14.475 0.210 ;
    END
  END rw0_wd_in[127]
  PIN rw0_wd_in[128]
    DIRECTION INPUT ;
    USE SIGNAL ;
    SHAPE ABUTMENT ;
    PORT
      LAYER metal2 ;
      RECT 14.785 0.000 14.855 0.210 ;
    END
  END rw0_wd_in[128]
  PIN rw0_wd_in[129]
    DIRECTION INPUT ;
    USE SIGNAL ;
    SHAPE ABUTMENT ;
    PORT
      LAYER metal2 ;
      RECT 15.165 0.000 15.235 0.210 ;
    END
  END rw0_wd_in[129]
  PIN rw0_wd_in[130]
    DIRECTION INPUT ;
    USE SIGNAL ;
    SHAPE ABUTMENT ;
    PORT
      LAYER metal2 ;
      RECT 15.545 0.000 15.615 0.210 ;
    END
  END rw0_wd_in[130]
  PIN rw0_wd_in[131]
    DIRECTION INPUT ;
    USE SIGNAL ;
    SHAPE ABUTMENT ;
    PORT
      LAYER metal2 ;
      RECT 15.925 0.000 15.995 0.210 ;
    END
  END rw0_wd_in[131]
  PIN rw0_wd_in[132]
    DIRECTION INPUT ;
    USE SIGNAL ;
    SHAPE ABUTMENT ;
    PORT
      LAYER metal2 ;
      RECT 16.305 0.000 16.375 0.210 ;
    END
  END rw0_wd_in[132]
  PIN rw0_wd_in[133]
    DIRECTION INPUT ;
    USE SIGNAL ;
    SHAPE ABUTMENT ;
    PORT
      LAYER metal2 ;
      RECT 16.685 0.000 16.755 0.210 ;
    END
  END rw0_wd_in[133]
  PIN rw0_wd_in[134]
    DIRECTION INPUT ;
    USE SIGNAL ;
    SHAPE ABUTMENT ;
    PORT
      LAYER metal2 ;
      RECT 17.065 0.000 17.135 0.210 ;
    END
  END rw0_wd_in[134]
  PIN rw0_wd_in[135]
    DIRECTION INPUT ;
    USE SIGNAL ;
    SHAPE ABUTMENT ;
    PORT
      LAYER metal2 ;
      RECT 17.445 0.000 17.515 0.210 ;
    END
  END rw0_wd_in[135]
  PIN rw0_wd_in[136]
    DIRECTION INPUT ;
    USE SIGNAL ;
    SHAPE ABUTMENT ;
    PORT
      LAYER metal2 ;
      RECT 17.825 0.000 17.895 0.210 ;
    END
  END rw0_wd_in[136]
  PIN rw0_wd_in[137]
    DIRECTION INPUT ;
    USE SIGNAL ;
    SHAPE ABUTMENT ;
    PORT
      LAYER metal2 ;
      RECT 18.205 0.000 18.275 0.210 ;
    END
  END rw0_wd_in[137]
  PIN rw0_wd_in[138]
    DIRECTION INPUT ;
    USE SIGNAL ;
    SHAPE ABUTMENT ;
    PORT
      LAYER metal2 ;
      RECT 18.585 0.000 18.655 0.210 ;
    END
  END rw0_wd_in[138]
  PIN rw0_wd_in[139]
    DIRECTION INPUT ;
    USE SIGNAL ;
    SHAPE ABUTMENT ;
    PORT
      LAYER metal2 ;
      RECT 18.965 0.000 19.035 0.210 ;
    END
  END rw0_wd_in[139]
  PIN rw0_wd_in[140]
    DIRECTION INPUT ;
    USE SIGNAL ;
    SHAPE ABUTMENT ;
    PORT
      LAYER metal2 ;
      RECT 19.345 0.000 19.415 0.210 ;
    END
  END rw0_wd_in[140]
  PIN rw0_wd_in[141]
    DIRECTION INPUT ;
    USE SIGNAL ;
    SHAPE ABUTMENT ;
    PORT
      LAYER metal2 ;
      RECT 19.725 0.000 19.795 0.210 ;
    END
  END rw0_wd_in[141]
  PIN rw0_wd_in[142]
    DIRECTION INPUT ;
    USE SIGNAL ;
    SHAPE ABUTMENT ;
    PORT
      LAYER metal2 ;
      RECT 20.105 0.000 20.175 0.210 ;
    END
  END rw0_wd_in[142]
  PIN rw0_wd_in[143]
    DIRECTION INPUT ;
    USE SIGNAL ;
    SHAPE ABUTMENT ;
    PORT
      LAYER metal2 ;
      RECT 20.485 0.000 20.555 0.210 ;
    END
  END rw0_wd_in[143]
  PIN rw0_wd_in[144]
    DIRECTION INPUT ;
    USE SIGNAL ;
    SHAPE ABUTMENT ;
    PORT
      LAYER metal2 ;
      RECT 20.865 0.000 20.935 0.210 ;
    END
  END rw0_wd_in[144]
  PIN rw0_wd_in[145]
    DIRECTION INPUT ;
    USE SIGNAL ;
    SHAPE ABUTMENT ;
    PORT
      LAYER metal2 ;
      RECT 21.245 0.000 21.315 0.210 ;
    END
  END rw0_wd_in[145]
  PIN rw0_wd_in[146]
    DIRECTION INPUT ;
    USE SIGNAL ;
    SHAPE ABUTMENT ;
    PORT
      LAYER metal2 ;
      RECT 21.625 0.000 21.695 0.210 ;
    END
  END rw0_wd_in[146]
  PIN rw0_wd_in[147]
    DIRECTION INPUT ;
    USE SIGNAL ;
    SHAPE ABUTMENT ;
    PORT
      LAYER metal2 ;
      RECT 22.005 0.000 22.075 0.210 ;
    END
  END rw0_wd_in[147]
  PIN rw0_wd_in[148]
    DIRECTION INPUT ;
    USE SIGNAL ;
    SHAPE ABUTMENT ;
    PORT
      LAYER metal2 ;
      RECT 22.385 0.000 22.455 0.210 ;
    END
  END rw0_wd_in[148]
  PIN rw0_wd_in[149]
    DIRECTION INPUT ;
    USE SIGNAL ;
    SHAPE ABUTMENT ;
    PORT
      LAYER metal2 ;
      RECT 22.765 0.000 22.835 0.210 ;
    END
  END rw0_wd_in[149]
  PIN rw0_wd_in[150]
    DIRECTION INPUT ;
    USE SIGNAL ;
    SHAPE ABUTMENT ;
    PORT
      LAYER metal2 ;
      RECT 23.145 0.000 23.215 0.210 ;
    END
  END rw0_wd_in[150]
  PIN rw0_wd_in[151]
    DIRECTION INPUT ;
    USE SIGNAL ;
    SHAPE ABUTMENT ;
    PORT
      LAYER metal2 ;
      RECT 23.525 0.000 23.595 0.210 ;
    END
  END rw0_wd_in[151]
  PIN rw0_wd_in[152]
    DIRECTION INPUT ;
    USE SIGNAL ;
    SHAPE ABUTMENT ;
    PORT
      LAYER metal2 ;
      RECT 23.905 0.000 23.975 0.210 ;
    END
  END rw0_wd_in[152]
  PIN rw0_wd_in[153]
    DIRECTION INPUT ;
    USE SIGNAL ;
    SHAPE ABUTMENT ;
    PORT
      LAYER metal2 ;
      RECT 24.285 0.000 24.355 0.210 ;
    END
  END rw0_wd_in[153]
  PIN rw0_wd_in[154]
    DIRECTION INPUT ;
    USE SIGNAL ;
    SHAPE ABUTMENT ;
    PORT
      LAYER metal2 ;
      RECT 24.665 0.000 24.735 0.210 ;
    END
  END rw0_wd_in[154]
  PIN rw0_wd_in[155]
    DIRECTION INPUT ;
    USE SIGNAL ;
    SHAPE ABUTMENT ;
    PORT
      LAYER metal2 ;
      RECT 25.045 0.000 25.115 0.210 ;
    END
  END rw0_wd_in[155]
  PIN rw0_wd_in[156]
    DIRECTION INPUT ;
    USE SIGNAL ;
    SHAPE ABUTMENT ;
    PORT
      LAYER metal2 ;
      RECT 25.425 0.000 25.495 0.210 ;
    END
  END rw0_wd_in[156]
  PIN rw0_wd_in[157]
    DIRECTION INPUT ;
    USE SIGNAL ;
    SHAPE ABUTMENT ;
    PORT
      LAYER metal2 ;
      RECT 25.805 0.000 25.875 0.210 ;
    END
  END rw0_wd_in[157]
  PIN rw0_wd_in[158]
    DIRECTION INPUT ;
    USE SIGNAL ;
    SHAPE ABUTMENT ;
    PORT
      LAYER metal2 ;
      RECT 26.185 0.000 26.255 0.210 ;
    END
  END rw0_wd_in[158]
  PIN rw0_wd_in[159]
    DIRECTION INPUT ;
    USE SIGNAL ;
    SHAPE ABUTMENT ;
    PORT
      LAYER metal2 ;
      RECT 26.565 0.000 26.635 0.210 ;
    END
  END rw0_wd_in[159]
  PIN rw0_wd_in[160]
    DIRECTION INPUT ;
    USE SIGNAL ;
    SHAPE ABUTMENT ;
    PORT
      LAYER metal2 ;
      RECT 26.945 0.000 27.015 0.210 ;
    END
  END rw0_wd_in[160]
  PIN rw0_wd_in[161]
    DIRECTION INPUT ;
    USE SIGNAL ;
    SHAPE ABUTMENT ;
    PORT
      LAYER metal2 ;
      RECT 27.325 0.000 27.395 0.210 ;
    END
  END rw0_wd_in[161]
  PIN rw0_wd_in[162]
    DIRECTION INPUT ;
    USE SIGNAL ;
    SHAPE ABUTMENT ;
    PORT
      LAYER metal2 ;
      RECT 27.705 0.000 27.775 0.210 ;
    END
  END rw0_wd_in[162]
  PIN rw0_wd_in[163]
    DIRECTION INPUT ;
    USE SIGNAL ;
    SHAPE ABUTMENT ;
    PORT
      LAYER metal2 ;
      RECT 28.085 0.000 28.155 0.210 ;
    END
  END rw0_wd_in[163]
  PIN rw0_wd_in[164]
    DIRECTION INPUT ;
    USE SIGNAL ;
    SHAPE ABUTMENT ;
    PORT
      LAYER metal2 ;
      RECT 28.465 0.000 28.535 0.210 ;
    END
  END rw0_wd_in[164]
  PIN rw0_wd_in[165]
    DIRECTION INPUT ;
    USE SIGNAL ;
    SHAPE ABUTMENT ;
    PORT
      LAYER metal2 ;
      RECT 28.845 0.000 28.915 0.210 ;
    END
  END rw0_wd_in[165]
  PIN rw0_wd_in[166]
    DIRECTION INPUT ;
    USE SIGNAL ;
    SHAPE ABUTMENT ;
    PORT
      LAYER metal2 ;
      RECT 29.225 0.000 29.295 0.210 ;
    END
  END rw0_wd_in[166]
  PIN rw0_wd_in[167]
    DIRECTION INPUT ;
    USE SIGNAL ;
    SHAPE ABUTMENT ;
    PORT
      LAYER metal2 ;
      RECT 29.605 0.000 29.675 0.210 ;
    END
  END rw0_wd_in[167]
  PIN rw0_wd_in[168]
    DIRECTION INPUT ;
    USE SIGNAL ;
    SHAPE ABUTMENT ;
    PORT
      LAYER metal2 ;
      RECT 29.985 0.000 30.055 0.210 ;
    END
  END rw0_wd_in[168]
  PIN rw0_wd_in[169]
    DIRECTION INPUT ;
    USE SIGNAL ;
    SHAPE ABUTMENT ;
    PORT
      LAYER metal2 ;
      RECT 30.365 0.000 30.435 0.210 ;
    END
  END rw0_wd_in[169]
  PIN rw0_wd_in[170]
    DIRECTION INPUT ;
    USE SIGNAL ;
    SHAPE ABUTMENT ;
    PORT
      LAYER metal2 ;
      RECT 30.745 0.000 30.815 0.210 ;
    END
  END rw0_wd_in[170]
  PIN rw0_wd_in[171]
    DIRECTION INPUT ;
    USE SIGNAL ;
    SHAPE ABUTMENT ;
    PORT
      LAYER metal2 ;
      RECT 31.125 0.000 31.195 0.210 ;
    END
  END rw0_wd_in[171]
  PIN rw0_wd_in[172]
    DIRECTION INPUT ;
    USE SIGNAL ;
    SHAPE ABUTMENT ;
    PORT
      LAYER metal2 ;
      RECT 31.505 0.000 31.575 0.210 ;
    END
  END rw0_wd_in[172]
  PIN rw0_wd_in[173]
    DIRECTION INPUT ;
    USE SIGNAL ;
    SHAPE ABUTMENT ;
    PORT
      LAYER metal2 ;
      RECT 31.885 0.000 31.955 0.210 ;
    END
  END rw0_wd_in[173]
  PIN rw0_wd_in[174]
    DIRECTION INPUT ;
    USE SIGNAL ;
    SHAPE ABUTMENT ;
    PORT
      LAYER metal2 ;
      RECT 32.265 0.000 32.335 0.210 ;
    END
  END rw0_wd_in[174]
  PIN rw0_wd_in[175]
    DIRECTION INPUT ;
    USE SIGNAL ;
    SHAPE ABUTMENT ;
    PORT
      LAYER metal2 ;
      RECT 32.645 0.000 32.715 0.210 ;
    END
  END rw0_wd_in[175]
  PIN rw0_wd_in[176]
    DIRECTION INPUT ;
    USE SIGNAL ;
    SHAPE ABUTMENT ;
    PORT
      LAYER metal2 ;
      RECT 33.025 0.000 33.095 0.210 ;
    END
  END rw0_wd_in[176]
  PIN rw0_wd_in[177]
    DIRECTION INPUT ;
    USE SIGNAL ;
    SHAPE ABUTMENT ;
    PORT
      LAYER metal2 ;
      RECT 33.405 0.000 33.475 0.210 ;
    END
  END rw0_wd_in[177]
  PIN rw0_wd_in[178]
    DIRECTION INPUT ;
    USE SIGNAL ;
    SHAPE ABUTMENT ;
    PORT
      LAYER metal2 ;
      RECT 33.785 0.000 33.855 0.210 ;
    END
  END rw0_wd_in[178]
  PIN rw0_wd_in[179]
    DIRECTION INPUT ;
    USE SIGNAL ;
    SHAPE ABUTMENT ;
    PORT
      LAYER metal2 ;
      RECT 34.165 0.000 34.235 0.210 ;
    END
  END rw0_wd_in[179]
  PIN rw0_wd_in[180]
    DIRECTION INPUT ;
    USE SIGNAL ;
    SHAPE ABUTMENT ;
    PORT
      LAYER metal2 ;
      RECT 34.545 0.000 34.615 0.210 ;
    END
  END rw0_wd_in[180]
  PIN rw0_wd_in[181]
    DIRECTION INPUT ;
    USE SIGNAL ;
    SHAPE ABUTMENT ;
    PORT
      LAYER metal2 ;
      RECT 34.925 0.000 34.995 0.210 ;
    END
  END rw0_wd_in[181]
  PIN rw0_wd_in[182]
    DIRECTION INPUT ;
    USE SIGNAL ;
    SHAPE ABUTMENT ;
    PORT
      LAYER metal2 ;
      RECT 35.305 0.000 35.375 0.210 ;
    END
  END rw0_wd_in[182]
  PIN rw0_wd_in[183]
    DIRECTION INPUT ;
    USE SIGNAL ;
    SHAPE ABUTMENT ;
    PORT
      LAYER metal2 ;
      RECT 35.685 0.000 35.755 0.210 ;
    END
  END rw0_wd_in[183]
  PIN rw0_rd_out[0]
    DIRECTION OUTPUT ;
    USE SIGNAL ;
    SHAPE ABUTMENT ;
    PORT
      LAYER metal2 ;
      RECT 36.065 0.000 36.135 0.210 ;
    END
  END rw0_rd_out[0]
  PIN rw0_rd_out[1]
    DIRECTION OUTPUT ;
    USE SIGNAL ;
    SHAPE ABUTMENT ;
    PORT
      LAYER metal2 ;
      RECT 36.445 0.000 36.515 0.210 ;
    END
  END rw0_rd_out[1]
  PIN rw0_rd_out[2]
    DIRECTION OUTPUT ;
    USE SIGNAL ;
    SHAPE ABUTMENT ;
    PORT
      LAYER metal2 ;
      RECT 36.825 0.000 36.895 0.210 ;
    END
  END rw0_rd_out[2]
  PIN rw0_rd_out[3]
    DIRECTION OUTPUT ;
    USE SIGNAL ;
    SHAPE ABUTMENT ;
    PORT
      LAYER metal2 ;
      RECT 37.205 0.000 37.275 0.210 ;
    END
  END rw0_rd_out[3]
  PIN rw0_rd_out[4]
    DIRECTION OUTPUT ;
    USE SIGNAL ;
    SHAPE ABUTMENT ;
    PORT
      LAYER metal2 ;
      RECT 37.585 0.000 37.655 0.210 ;
    END
  END rw0_rd_out[4]
  PIN rw0_rd_out[5]
    DIRECTION OUTPUT ;
    USE SIGNAL ;
    SHAPE ABUTMENT ;
    PORT
      LAYER metal2 ;
      RECT 37.965 0.000 38.035 0.210 ;
    END
  END rw0_rd_out[5]
  PIN rw0_rd_out[6]
    DIRECTION OUTPUT ;
    USE SIGNAL ;
    SHAPE ABUTMENT ;
    PORT
      LAYER metal2 ;
      RECT 38.345 0.000 38.415 0.210 ;
    END
  END rw0_rd_out[6]
  PIN rw0_rd_out[7]
    DIRECTION OUTPUT ;
    USE SIGNAL ;
    SHAPE ABUTMENT ;
    PORT
      LAYER metal2 ;
      RECT 38.725 0.000 38.795 0.210 ;
    END
  END rw0_rd_out[7]
  PIN rw0_rd_out[8]
    DIRECTION OUTPUT ;
    USE SIGNAL ;
    SHAPE ABUTMENT ;
    PORT
      LAYER metal2 ;
      RECT 39.105 0.000 39.175 0.210 ;
    END
  END rw0_rd_out[8]
  PIN rw0_rd_out[9]
    DIRECTION OUTPUT ;
    USE SIGNAL ;
    SHAPE ABUTMENT ;
    PORT
      LAYER metal2 ;
      RECT 39.485 0.000 39.555 0.210 ;
    END
  END rw0_rd_out[9]
  PIN rw0_rd_out[10]
    DIRECTION OUTPUT ;
    USE SIGNAL ;
    SHAPE ABUTMENT ;
    PORT
      LAYER metal2 ;
      RECT 39.865 0.000 39.935 0.210 ;
    END
  END rw0_rd_out[10]
  PIN rw0_rd_out[11]
    DIRECTION OUTPUT ;
    USE SIGNAL ;
    SHAPE ABUTMENT ;
    PORT
      LAYER metal2 ;
      RECT 40.245 0.000 40.315 0.210 ;
    END
  END rw0_rd_out[11]
  PIN rw0_rd_out[12]
    DIRECTION OUTPUT ;
    USE SIGNAL ;
    SHAPE ABUTMENT ;
    PORT
      LAYER metal2 ;
      RECT 40.625 0.000 40.695 0.210 ;
    END
  END rw0_rd_out[12]
  PIN rw0_rd_out[13]
    DIRECTION OUTPUT ;
    USE SIGNAL ;
    SHAPE ABUTMENT ;
    PORT
      LAYER metal2 ;
      RECT 41.005 0.000 41.075 0.210 ;
    END
  END rw0_rd_out[13]
  PIN rw0_rd_out[14]
    DIRECTION OUTPUT ;
    USE SIGNAL ;
    SHAPE ABUTMENT ;
    PORT
      LAYER metal2 ;
      RECT 41.385 0.000 41.455 0.210 ;
    END
  END rw0_rd_out[14]
  PIN rw0_rd_out[15]
    DIRECTION OUTPUT ;
    USE SIGNAL ;
    SHAPE ABUTMENT ;
    PORT
      LAYER metal2 ;
      RECT 41.765 0.000 41.835 0.210 ;
    END
  END rw0_rd_out[15]
  PIN rw0_rd_out[16]
    DIRECTION OUTPUT ;
    USE SIGNAL ;
    SHAPE ABUTMENT ;
    PORT
      LAYER metal2 ;
      RECT 42.145 0.000 42.215 0.210 ;
    END
  END rw0_rd_out[16]
  PIN rw0_rd_out[17]
    DIRECTION OUTPUT ;
    USE SIGNAL ;
    SHAPE ABUTMENT ;
    PORT
      LAYER metal2 ;
      RECT 42.525 0.000 42.595 0.210 ;
    END
  END rw0_rd_out[17]
  PIN rw0_rd_out[18]
    DIRECTION OUTPUT ;
    USE SIGNAL ;
    SHAPE ABUTMENT ;
    PORT
      LAYER metal2 ;
      RECT 42.905 0.000 42.975 0.210 ;
    END
  END rw0_rd_out[18]
  PIN rw0_rd_out[19]
    DIRECTION OUTPUT ;
    USE SIGNAL ;
    SHAPE ABUTMENT ;
    PORT
      LAYER metal2 ;
      RECT 43.285 0.000 43.355 0.210 ;
    END
  END rw0_rd_out[19]
  PIN rw0_rd_out[20]
    DIRECTION OUTPUT ;
    USE SIGNAL ;
    SHAPE ABUTMENT ;
    PORT
      LAYER metal2 ;
      RECT 43.665 0.000 43.735 0.210 ;
    END
  END rw0_rd_out[20]
  PIN rw0_rd_out[21]
    DIRECTION OUTPUT ;
    USE SIGNAL ;
    SHAPE ABUTMENT ;
    PORT
      LAYER metal2 ;
      RECT 44.045 0.000 44.115 0.210 ;
    END
  END rw0_rd_out[21]
  PIN rw0_rd_out[22]
    DIRECTION OUTPUT ;
    USE SIGNAL ;
    SHAPE ABUTMENT ;
    PORT
      LAYER metal2 ;
      RECT 44.425 0.000 44.495 0.210 ;
    END
  END rw0_rd_out[22]
  PIN rw0_rd_out[23]
    DIRECTION OUTPUT ;
    USE SIGNAL ;
    SHAPE ABUTMENT ;
    PORT
      LAYER metal2 ;
      RECT 44.805 0.000 44.875 0.210 ;
    END
  END rw0_rd_out[23]
  PIN rw0_rd_out[24]
    DIRECTION OUTPUT ;
    USE SIGNAL ;
    SHAPE ABUTMENT ;
    PORT
      LAYER metal2 ;
      RECT 45.185 0.000 45.255 0.210 ;
    END
  END rw0_rd_out[24]
  PIN rw0_rd_out[25]
    DIRECTION OUTPUT ;
    USE SIGNAL ;
    SHAPE ABUTMENT ;
    PORT
      LAYER metal2 ;
      RECT 45.565 0.000 45.635 0.210 ;
    END
  END rw0_rd_out[25]
  PIN rw0_rd_out[26]
    DIRECTION OUTPUT ;
    USE SIGNAL ;
    SHAPE ABUTMENT ;
    PORT
      LAYER metal2 ;
      RECT 45.945 0.000 46.015 0.210 ;
    END
  END rw0_rd_out[26]
  PIN rw0_rd_out[27]
    DIRECTION OUTPUT ;
    USE SIGNAL ;
    SHAPE ABUTMENT ;
    PORT
      LAYER metal2 ;
      RECT 46.325 0.000 46.395 0.210 ;
    END
  END rw0_rd_out[27]
  PIN rw0_rd_out[28]
    DIRECTION OUTPUT ;
    USE SIGNAL ;
    SHAPE ABUTMENT ;
    PORT
      LAYER metal2 ;
      RECT 46.705 0.000 46.775 0.210 ;
    END
  END rw0_rd_out[28]
  PIN rw0_rd_out[29]
    DIRECTION OUTPUT ;
    USE SIGNAL ;
    SHAPE ABUTMENT ;
    PORT
      LAYER metal2 ;
      RECT 47.085 0.000 47.155 0.210 ;
    END
  END rw0_rd_out[29]
  PIN rw0_rd_out[30]
    DIRECTION OUTPUT ;
    USE SIGNAL ;
    SHAPE ABUTMENT ;
    PORT
      LAYER metal2 ;
      RECT 47.465 0.000 47.535 0.210 ;
    END
  END rw0_rd_out[30]
  PIN rw0_rd_out[31]
    DIRECTION OUTPUT ;
    USE SIGNAL ;
    SHAPE ABUTMENT ;
    PORT
      LAYER metal2 ;
      RECT 47.845 0.000 47.915 0.210 ;
    END
  END rw0_rd_out[31]
  PIN rw0_rd_out[32]
    DIRECTION OUTPUT ;
    USE SIGNAL ;
    SHAPE ABUTMENT ;
    PORT
      LAYER metal2 ;
      RECT 48.225 0.000 48.295 0.210 ;
    END
  END rw0_rd_out[32]
  PIN rw0_rd_out[33]
    DIRECTION OUTPUT ;
    USE SIGNAL ;
    SHAPE ABUTMENT ;
    PORT
      LAYER metal2 ;
      RECT 48.605 0.000 48.675 0.210 ;
    END
  END rw0_rd_out[33]
  PIN rw0_rd_out[34]
    DIRECTION OUTPUT ;
    USE SIGNAL ;
    SHAPE ABUTMENT ;
    PORT
      LAYER metal2 ;
      RECT 48.985 0.000 49.055 0.210 ;
    END
  END rw0_rd_out[34]
  PIN rw0_rd_out[35]
    DIRECTION OUTPUT ;
    USE SIGNAL ;
    SHAPE ABUTMENT ;
    PORT
      LAYER metal2 ;
      RECT 49.365 0.000 49.435 0.210 ;
    END
  END rw0_rd_out[35]
  PIN rw0_rd_out[36]
    DIRECTION OUTPUT ;
    USE SIGNAL ;
    SHAPE ABUTMENT ;
    PORT
      LAYER metal2 ;
      RECT 49.745 0.000 49.815 0.210 ;
    END
  END rw0_rd_out[36]
  PIN rw0_rd_out[37]
    DIRECTION OUTPUT ;
    USE SIGNAL ;
    SHAPE ABUTMENT ;
    PORT
      LAYER metal2 ;
      RECT 50.125 0.000 50.195 0.210 ;
    END
  END rw0_rd_out[37]
  PIN rw0_rd_out[38]
    DIRECTION OUTPUT ;
    USE SIGNAL ;
    SHAPE ABUTMENT ;
    PORT
      LAYER metal2 ;
      RECT 50.505 0.000 50.575 0.210 ;
    END
  END rw0_rd_out[38]
  PIN rw0_rd_out[39]
    DIRECTION OUTPUT ;
    USE SIGNAL ;
    SHAPE ABUTMENT ;
    PORT
      LAYER metal2 ;
      RECT 50.885 0.000 50.955 0.210 ;
    END
  END rw0_rd_out[39]
  PIN rw0_rd_out[40]
    DIRECTION OUTPUT ;
    USE SIGNAL ;
    SHAPE ABUTMENT ;
    PORT
      LAYER metal2 ;
      RECT 51.265 0.000 51.335 0.210 ;
    END
  END rw0_rd_out[40]
  PIN rw0_rd_out[41]
    DIRECTION OUTPUT ;
    USE SIGNAL ;
    SHAPE ABUTMENT ;
    PORT
      LAYER metal2 ;
      RECT 51.645 0.000 51.715 0.210 ;
    END
  END rw0_rd_out[41]
  PIN rw0_rd_out[42]
    DIRECTION OUTPUT ;
    USE SIGNAL ;
    SHAPE ABUTMENT ;
    PORT
      LAYER metal2 ;
      RECT 52.025 0.000 52.095 0.210 ;
    END
  END rw0_rd_out[42]
  PIN rw0_rd_out[43]
    DIRECTION OUTPUT ;
    USE SIGNAL ;
    SHAPE ABUTMENT ;
    PORT
      LAYER metal2 ;
      RECT 52.405 0.000 52.475 0.210 ;
    END
  END rw0_rd_out[43]
  PIN rw0_rd_out[44]
    DIRECTION OUTPUT ;
    USE SIGNAL ;
    SHAPE ABUTMENT ;
    PORT
      LAYER metal2 ;
      RECT 52.785 0.000 52.855 0.210 ;
    END
  END rw0_rd_out[44]
  PIN rw0_rd_out[45]
    DIRECTION OUTPUT ;
    USE SIGNAL ;
    SHAPE ABUTMENT ;
    PORT
      LAYER metal2 ;
      RECT 53.165 0.000 53.235 0.210 ;
    END
  END rw0_rd_out[45]
  PIN rw0_rd_out[46]
    DIRECTION OUTPUT ;
    USE SIGNAL ;
    SHAPE ABUTMENT ;
    PORT
      LAYER metal2 ;
      RECT 53.545 0.000 53.615 0.210 ;
    END
  END rw0_rd_out[46]
  PIN rw0_rd_out[47]
    DIRECTION OUTPUT ;
    USE SIGNAL ;
    SHAPE ABUTMENT ;
    PORT
      LAYER metal2 ;
      RECT 53.925 0.000 53.995 0.210 ;
    END
  END rw0_rd_out[47]
  PIN rw0_rd_out[48]
    DIRECTION OUTPUT ;
    USE SIGNAL ;
    SHAPE ABUTMENT ;
    PORT
      LAYER metal2 ;
      RECT 54.305 0.000 54.375 0.210 ;
    END
  END rw0_rd_out[48]
  PIN rw0_rd_out[49]
    DIRECTION OUTPUT ;
    USE SIGNAL ;
    SHAPE ABUTMENT ;
    PORT
      LAYER metal2 ;
      RECT 54.685 0.000 54.755 0.210 ;
    END
  END rw0_rd_out[49]
  PIN rw0_rd_out[50]
    DIRECTION OUTPUT ;
    USE SIGNAL ;
    SHAPE ABUTMENT ;
    PORT
      LAYER metal2 ;
      RECT 55.065 0.000 55.135 0.210 ;
    END
  END rw0_rd_out[50]
  PIN rw0_rd_out[51]
    DIRECTION OUTPUT ;
    USE SIGNAL ;
    SHAPE ABUTMENT ;
    PORT
      LAYER metal2 ;
      RECT 55.445 0.000 55.515 0.210 ;
    END
  END rw0_rd_out[51]
  PIN rw0_rd_out[52]
    DIRECTION OUTPUT ;
    USE SIGNAL ;
    SHAPE ABUTMENT ;
    PORT
      LAYER metal2 ;
      RECT 55.825 0.000 55.895 0.210 ;
    END
  END rw0_rd_out[52]
  PIN rw0_rd_out[53]
    DIRECTION OUTPUT ;
    USE SIGNAL ;
    SHAPE ABUTMENT ;
    PORT
      LAYER metal2 ;
      RECT 56.205 0.000 56.275 0.210 ;
    END
  END rw0_rd_out[53]
  PIN rw0_rd_out[54]
    DIRECTION OUTPUT ;
    USE SIGNAL ;
    SHAPE ABUTMENT ;
    PORT
      LAYER metal2 ;
      RECT 56.585 0.000 56.655 0.210 ;
    END
  END rw0_rd_out[54]
  PIN rw0_rd_out[55]
    DIRECTION OUTPUT ;
    USE SIGNAL ;
    SHAPE ABUTMENT ;
    PORT
      LAYER metal2 ;
      RECT 56.965 0.000 57.035 0.210 ;
    END
  END rw0_rd_out[55]
  PIN rw0_rd_out[56]
    DIRECTION OUTPUT ;
    USE SIGNAL ;
    SHAPE ABUTMENT ;
    PORT
      LAYER metal2 ;
      RECT 57.345 0.000 57.415 0.210 ;
    END
  END rw0_rd_out[56]
  PIN rw0_rd_out[57]
    DIRECTION OUTPUT ;
    USE SIGNAL ;
    SHAPE ABUTMENT ;
    PORT
      LAYER metal2 ;
      RECT 57.725 0.000 57.795 0.210 ;
    END
  END rw0_rd_out[57]
  PIN rw0_rd_out[58]
    DIRECTION OUTPUT ;
    USE SIGNAL ;
    SHAPE ABUTMENT ;
    PORT
      LAYER metal2 ;
      RECT 58.105 0.000 58.175 0.210 ;
    END
  END rw0_rd_out[58]
  PIN rw0_rd_out[59]
    DIRECTION OUTPUT ;
    USE SIGNAL ;
    SHAPE ABUTMENT ;
    PORT
      LAYER metal2 ;
      RECT 58.485 0.000 58.555 0.210 ;
    END
  END rw0_rd_out[59]
  PIN rw0_rd_out[60]
    DIRECTION OUTPUT ;
    USE SIGNAL ;
    SHAPE ABUTMENT ;
    PORT
      LAYER metal2 ;
      RECT 58.865 0.000 58.935 0.210 ;
    END
  END rw0_rd_out[60]
  PIN rw0_rd_out[61]
    DIRECTION OUTPUT ;
    USE SIGNAL ;
    SHAPE ABUTMENT ;
    PORT
      LAYER metal2 ;
      RECT 59.245 0.000 59.315 0.210 ;
    END
  END rw0_rd_out[61]
  PIN rw0_rd_out[62]
    DIRECTION OUTPUT ;
    USE SIGNAL ;
    SHAPE ABUTMENT ;
    PORT
      LAYER metal2 ;
      RECT 59.625 0.000 59.695 0.210 ;
    END
  END rw0_rd_out[62]
  PIN rw0_rd_out[63]
    DIRECTION OUTPUT ;
    USE SIGNAL ;
    SHAPE ABUTMENT ;
    PORT
      LAYER metal2 ;
      RECT 60.005 0.000 60.075 0.210 ;
    END
  END rw0_rd_out[63]
  PIN rw0_rd_out[64]
    DIRECTION OUTPUT ;
    USE SIGNAL ;
    SHAPE ABUTMENT ;
    PORT
      LAYER metal2 ;
      RECT 60.385 0.000 60.455 0.210 ;
    END
  END rw0_rd_out[64]
  PIN rw0_rd_out[65]
    DIRECTION OUTPUT ;
    USE SIGNAL ;
    SHAPE ABUTMENT ;
    PORT
      LAYER metal2 ;
      RECT 60.765 0.000 60.835 0.210 ;
    END
  END rw0_rd_out[65]
  PIN rw0_rd_out[66]
    DIRECTION OUTPUT ;
    USE SIGNAL ;
    SHAPE ABUTMENT ;
    PORT
      LAYER metal2 ;
      RECT 61.145 0.000 61.215 0.210 ;
    END
  END rw0_rd_out[66]
  PIN rw0_rd_out[67]
    DIRECTION OUTPUT ;
    USE SIGNAL ;
    SHAPE ABUTMENT ;
    PORT
      LAYER metal2 ;
      RECT 61.525 0.000 61.595 0.210 ;
    END
  END rw0_rd_out[67]
  PIN rw0_rd_out[68]
    DIRECTION OUTPUT ;
    USE SIGNAL ;
    SHAPE ABUTMENT ;
    PORT
      LAYER metal2 ;
      RECT 61.905 0.000 61.975 0.210 ;
    END
  END rw0_rd_out[68]
  PIN rw0_rd_out[69]
    DIRECTION OUTPUT ;
    USE SIGNAL ;
    SHAPE ABUTMENT ;
    PORT
      LAYER metal2 ;
      RECT 62.285 0.000 62.355 0.210 ;
    END
  END rw0_rd_out[69]
  PIN rw0_rd_out[70]
    DIRECTION OUTPUT ;
    USE SIGNAL ;
    SHAPE ABUTMENT ;
    PORT
      LAYER metal2 ;
      RECT 62.665 0.000 62.735 0.210 ;
    END
  END rw0_rd_out[70]
  PIN rw0_rd_out[71]
    DIRECTION OUTPUT ;
    USE SIGNAL ;
    SHAPE ABUTMENT ;
    PORT
      LAYER metal2 ;
      RECT 63.045 0.000 63.115 0.210 ;
    END
  END rw0_rd_out[71]
  PIN rw0_rd_out[72]
    DIRECTION OUTPUT ;
    USE SIGNAL ;
    SHAPE ABUTMENT ;
    PORT
      LAYER metal2 ;
      RECT 63.425 0.000 63.495 0.210 ;
    END
  END rw0_rd_out[72]
  PIN rw0_rd_out[73]
    DIRECTION OUTPUT ;
    USE SIGNAL ;
    SHAPE ABUTMENT ;
    PORT
      LAYER metal2 ;
      RECT 63.805 0.000 63.875 0.210 ;
    END
  END rw0_rd_out[73]
  PIN rw0_rd_out[74]
    DIRECTION OUTPUT ;
    USE SIGNAL ;
    SHAPE ABUTMENT ;
    PORT
      LAYER metal2 ;
      RECT 64.185 0.000 64.255 0.210 ;
    END
  END rw0_rd_out[74]
  PIN rw0_rd_out[75]
    DIRECTION OUTPUT ;
    USE SIGNAL ;
    SHAPE ABUTMENT ;
    PORT
      LAYER metal2 ;
      RECT 64.565 0.000 64.635 0.210 ;
    END
  END rw0_rd_out[75]
  PIN rw0_rd_out[76]
    DIRECTION OUTPUT ;
    USE SIGNAL ;
    SHAPE ABUTMENT ;
    PORT
      LAYER metal2 ;
      RECT 64.945 0.000 65.015 0.210 ;
    END
  END rw0_rd_out[76]
  PIN rw0_rd_out[77]
    DIRECTION OUTPUT ;
    USE SIGNAL ;
    SHAPE ABUTMENT ;
    PORT
      LAYER metal2 ;
      RECT 65.325 0.000 65.395 0.210 ;
    END
  END rw0_rd_out[77]
  PIN rw0_rd_out[78]
    DIRECTION OUTPUT ;
    USE SIGNAL ;
    SHAPE ABUTMENT ;
    PORT
      LAYER metal2 ;
      RECT 65.705 0.000 65.775 0.210 ;
    END
  END rw0_rd_out[78]
  PIN rw0_rd_out[79]
    DIRECTION OUTPUT ;
    USE SIGNAL ;
    SHAPE ABUTMENT ;
    PORT
      LAYER metal2 ;
      RECT 66.085 0.000 66.155 0.210 ;
    END
  END rw0_rd_out[79]
  PIN rw0_rd_out[80]
    DIRECTION OUTPUT ;
    USE SIGNAL ;
    SHAPE ABUTMENT ;
    PORT
      LAYER metal2 ;
      RECT 66.465 0.000 66.535 0.210 ;
    END
  END rw0_rd_out[80]
  PIN rw0_rd_out[81]
    DIRECTION OUTPUT ;
    USE SIGNAL ;
    SHAPE ABUTMENT ;
    PORT
      LAYER metal2 ;
      RECT 66.845 0.000 66.915 0.210 ;
    END
  END rw0_rd_out[81]
  PIN rw0_rd_out[82]
    DIRECTION OUTPUT ;
    USE SIGNAL ;
    SHAPE ABUTMENT ;
    PORT
      LAYER metal2 ;
      RECT 67.225 0.000 67.295 0.210 ;
    END
  END rw0_rd_out[82]
  PIN rw0_rd_out[83]
    DIRECTION OUTPUT ;
    USE SIGNAL ;
    SHAPE ABUTMENT ;
    PORT
      LAYER metal2 ;
      RECT 67.605 0.000 67.675 0.210 ;
    END
  END rw0_rd_out[83]
  PIN rw0_rd_out[84]
    DIRECTION OUTPUT ;
    USE SIGNAL ;
    SHAPE ABUTMENT ;
    PORT
      LAYER metal2 ;
      RECT 67.985 0.000 68.055 0.210 ;
    END
  END rw0_rd_out[84]
  PIN rw0_rd_out[85]
    DIRECTION OUTPUT ;
    USE SIGNAL ;
    SHAPE ABUTMENT ;
    PORT
      LAYER metal2 ;
      RECT 68.365 0.000 68.435 0.210 ;
    END
  END rw0_rd_out[85]
  PIN rw0_rd_out[86]
    DIRECTION OUTPUT ;
    USE SIGNAL ;
    SHAPE ABUTMENT ;
    PORT
      LAYER metal2 ;
      RECT 68.745 0.000 68.815 0.210 ;
    END
  END rw0_rd_out[86]
  PIN rw0_rd_out[87]
    DIRECTION OUTPUT ;
    USE SIGNAL ;
    SHAPE ABUTMENT ;
    PORT
      LAYER metal2 ;
      RECT 69.125 0.000 69.195 0.210 ;
    END
  END rw0_rd_out[87]
  PIN rw0_rd_out[88]
    DIRECTION OUTPUT ;
    USE SIGNAL ;
    SHAPE ABUTMENT ;
    PORT
      LAYER metal2 ;
      RECT 69.505 0.000 69.575 0.210 ;
    END
  END rw0_rd_out[88]
  PIN rw0_rd_out[89]
    DIRECTION OUTPUT ;
    USE SIGNAL ;
    SHAPE ABUTMENT ;
    PORT
      LAYER metal2 ;
      RECT 69.885 0.000 69.955 0.210 ;
    END
  END rw0_rd_out[89]
  PIN rw0_rd_out[90]
    DIRECTION OUTPUT ;
    USE SIGNAL ;
    SHAPE ABUTMENT ;
    PORT
      LAYER metal2 ;
      RECT 70.265 0.000 70.335 0.210 ;
    END
  END rw0_rd_out[90]
  PIN rw0_rd_out[91]
    DIRECTION OUTPUT ;
    USE SIGNAL ;
    SHAPE ABUTMENT ;
    PORT
      LAYER metal2 ;
      RECT 70.645 0.000 70.715 0.210 ;
    END
  END rw0_rd_out[91]
  PIN rw0_rd_out[92]
    DIRECTION OUTPUT ;
    USE SIGNAL ;
    SHAPE ABUTMENT ;
    PORT
      LAYER metal2 ;
      RECT 36.065 153.790 36.135 154.000 ;
    END
  END rw0_rd_out[92]
  PIN rw0_rd_out[93]
    DIRECTION OUTPUT ;
    USE SIGNAL ;
    SHAPE ABUTMENT ;
    PORT
      LAYER metal2 ;
      RECT 36.445 153.790 36.515 154.000 ;
    END
  END rw0_rd_out[93]
  PIN rw0_rd_out[94]
    DIRECTION OUTPUT ;
    USE SIGNAL ;
    SHAPE ABUTMENT ;
    PORT
      LAYER metal2 ;
      RECT 36.825 153.790 36.895 154.000 ;
    END
  END rw0_rd_out[94]
  PIN rw0_rd_out[95]
    DIRECTION OUTPUT ;
    USE SIGNAL ;
    SHAPE ABUTMENT ;
    PORT
      LAYER metal2 ;
      RECT 37.205 153.790 37.275 154.000 ;
    END
  END rw0_rd_out[95]
  PIN rw0_rd_out[96]
    DIRECTION OUTPUT ;
    USE SIGNAL ;
    SHAPE ABUTMENT ;
    PORT
      LAYER metal2 ;
      RECT 37.585 153.790 37.655 154.000 ;
    END
  END rw0_rd_out[96]
  PIN rw0_rd_out[97]
    DIRECTION OUTPUT ;
    USE SIGNAL ;
    SHAPE ABUTMENT ;
    PORT
      LAYER metal2 ;
      RECT 37.965 153.790 38.035 154.000 ;
    END
  END rw0_rd_out[97]
  PIN rw0_rd_out[98]
    DIRECTION OUTPUT ;
    USE SIGNAL ;
    SHAPE ABUTMENT ;
    PORT
      LAYER metal2 ;
      RECT 38.345 153.790 38.415 154.000 ;
    END
  END rw0_rd_out[98]
  PIN rw0_rd_out[99]
    DIRECTION OUTPUT ;
    USE SIGNAL ;
    SHAPE ABUTMENT ;
    PORT
      LAYER metal2 ;
      RECT 38.725 153.790 38.795 154.000 ;
    END
  END rw0_rd_out[99]
  PIN rw0_rd_out[100]
    DIRECTION OUTPUT ;
    USE SIGNAL ;
    SHAPE ABUTMENT ;
    PORT
      LAYER metal2 ;
      RECT 39.105 153.790 39.175 154.000 ;
    END
  END rw0_rd_out[100]
  PIN rw0_rd_out[101]
    DIRECTION OUTPUT ;
    USE SIGNAL ;
    SHAPE ABUTMENT ;
    PORT
      LAYER metal2 ;
      RECT 39.485 153.790 39.555 154.000 ;
    END
  END rw0_rd_out[101]
  PIN rw0_rd_out[102]
    DIRECTION OUTPUT ;
    USE SIGNAL ;
    SHAPE ABUTMENT ;
    PORT
      LAYER metal2 ;
      RECT 39.865 153.790 39.935 154.000 ;
    END
  END rw0_rd_out[102]
  PIN rw0_rd_out[103]
    DIRECTION OUTPUT ;
    USE SIGNAL ;
    SHAPE ABUTMENT ;
    PORT
      LAYER metal2 ;
      RECT 40.245 153.790 40.315 154.000 ;
    END
  END rw0_rd_out[103]
  PIN rw0_rd_out[104]
    DIRECTION OUTPUT ;
    USE SIGNAL ;
    SHAPE ABUTMENT ;
    PORT
      LAYER metal2 ;
      RECT 40.625 153.790 40.695 154.000 ;
    END
  END rw0_rd_out[104]
  PIN rw0_rd_out[105]
    DIRECTION OUTPUT ;
    USE SIGNAL ;
    SHAPE ABUTMENT ;
    PORT
      LAYER metal2 ;
      RECT 41.005 153.790 41.075 154.000 ;
    END
  END rw0_rd_out[105]
  PIN rw0_rd_out[106]
    DIRECTION OUTPUT ;
    USE SIGNAL ;
    SHAPE ABUTMENT ;
    PORT
      LAYER metal2 ;
      RECT 41.385 153.790 41.455 154.000 ;
    END
  END rw0_rd_out[106]
  PIN rw0_rd_out[107]
    DIRECTION OUTPUT ;
    USE SIGNAL ;
    SHAPE ABUTMENT ;
    PORT
      LAYER metal2 ;
      RECT 41.765 153.790 41.835 154.000 ;
    END
  END rw0_rd_out[107]
  PIN rw0_rd_out[108]
    DIRECTION OUTPUT ;
    USE SIGNAL ;
    SHAPE ABUTMENT ;
    PORT
      LAYER metal2 ;
      RECT 42.145 153.790 42.215 154.000 ;
    END
  END rw0_rd_out[108]
  PIN rw0_rd_out[109]
    DIRECTION OUTPUT ;
    USE SIGNAL ;
    SHAPE ABUTMENT ;
    PORT
      LAYER metal2 ;
      RECT 42.525 153.790 42.595 154.000 ;
    END
  END rw0_rd_out[109]
  PIN rw0_rd_out[110]
    DIRECTION OUTPUT ;
    USE SIGNAL ;
    SHAPE ABUTMENT ;
    PORT
      LAYER metal2 ;
      RECT 42.905 153.790 42.975 154.000 ;
    END
  END rw0_rd_out[110]
  PIN rw0_rd_out[111]
    DIRECTION OUTPUT ;
    USE SIGNAL ;
    SHAPE ABUTMENT ;
    PORT
      LAYER metal2 ;
      RECT 43.285 153.790 43.355 154.000 ;
    END
  END rw0_rd_out[111]
  PIN rw0_rd_out[112]
    DIRECTION OUTPUT ;
    USE SIGNAL ;
    SHAPE ABUTMENT ;
    PORT
      LAYER metal2 ;
      RECT 43.665 153.790 43.735 154.000 ;
    END
  END rw0_rd_out[112]
  PIN rw0_rd_out[113]
    DIRECTION OUTPUT ;
    USE SIGNAL ;
    SHAPE ABUTMENT ;
    PORT
      LAYER metal2 ;
      RECT 44.045 153.790 44.115 154.000 ;
    END
  END rw0_rd_out[113]
  PIN rw0_rd_out[114]
    DIRECTION OUTPUT ;
    USE SIGNAL ;
    SHAPE ABUTMENT ;
    PORT
      LAYER metal2 ;
      RECT 44.425 153.790 44.495 154.000 ;
    END
  END rw0_rd_out[114]
  PIN rw0_rd_out[115]
    DIRECTION OUTPUT ;
    USE SIGNAL ;
    SHAPE ABUTMENT ;
    PORT
      LAYER metal2 ;
      RECT 44.805 153.790 44.875 154.000 ;
    END
  END rw0_rd_out[115]
  PIN rw0_rd_out[116]
    DIRECTION OUTPUT ;
    USE SIGNAL ;
    SHAPE ABUTMENT ;
    PORT
      LAYER metal2 ;
      RECT 45.185 153.790 45.255 154.000 ;
    END
  END rw0_rd_out[116]
  PIN rw0_rd_out[117]
    DIRECTION OUTPUT ;
    USE SIGNAL ;
    SHAPE ABUTMENT ;
    PORT
      LAYER metal2 ;
      RECT 45.565 153.790 45.635 154.000 ;
    END
  END rw0_rd_out[117]
  PIN rw0_rd_out[118]
    DIRECTION OUTPUT ;
    USE SIGNAL ;
    SHAPE ABUTMENT ;
    PORT
      LAYER metal2 ;
      RECT 45.945 153.790 46.015 154.000 ;
    END
  END rw0_rd_out[118]
  PIN rw0_rd_out[119]
    DIRECTION OUTPUT ;
    USE SIGNAL ;
    SHAPE ABUTMENT ;
    PORT
      LAYER metal2 ;
      RECT 46.325 153.790 46.395 154.000 ;
    END
  END rw0_rd_out[119]
  PIN rw0_rd_out[120]
    DIRECTION OUTPUT ;
    USE SIGNAL ;
    SHAPE ABUTMENT ;
    PORT
      LAYER metal2 ;
      RECT 46.705 153.790 46.775 154.000 ;
    END
  END rw0_rd_out[120]
  PIN rw0_rd_out[121]
    DIRECTION OUTPUT ;
    USE SIGNAL ;
    SHAPE ABUTMENT ;
    PORT
      LAYER metal2 ;
      RECT 47.085 153.790 47.155 154.000 ;
    END
  END rw0_rd_out[121]
  PIN rw0_rd_out[122]
    DIRECTION OUTPUT ;
    USE SIGNAL ;
    SHAPE ABUTMENT ;
    PORT
      LAYER metal2 ;
      RECT 47.465 153.790 47.535 154.000 ;
    END
  END rw0_rd_out[122]
  PIN rw0_rd_out[123]
    DIRECTION OUTPUT ;
    USE SIGNAL ;
    SHAPE ABUTMENT ;
    PORT
      LAYER metal2 ;
      RECT 47.845 153.790 47.915 154.000 ;
    END
  END rw0_rd_out[123]
  PIN rw0_rd_out[124]
    DIRECTION OUTPUT ;
    USE SIGNAL ;
    SHAPE ABUTMENT ;
    PORT
      LAYER metal2 ;
      RECT 48.225 153.790 48.295 154.000 ;
    END
  END rw0_rd_out[124]
  PIN rw0_rd_out[125]
    DIRECTION OUTPUT ;
    USE SIGNAL ;
    SHAPE ABUTMENT ;
    PORT
      LAYER metal2 ;
      RECT 48.605 153.790 48.675 154.000 ;
    END
  END rw0_rd_out[125]
  PIN rw0_rd_out[126]
    DIRECTION OUTPUT ;
    USE SIGNAL ;
    SHAPE ABUTMENT ;
    PORT
      LAYER metal2 ;
      RECT 48.985 153.790 49.055 154.000 ;
    END
  END rw0_rd_out[126]
  PIN rw0_rd_out[127]
    DIRECTION OUTPUT ;
    USE SIGNAL ;
    SHAPE ABUTMENT ;
    PORT
      LAYER metal2 ;
      RECT 49.365 153.790 49.435 154.000 ;
    END
  END rw0_rd_out[127]
  PIN rw0_rd_out[128]
    DIRECTION OUTPUT ;
    USE SIGNAL ;
    SHAPE ABUTMENT ;
    PORT
      LAYER metal2 ;
      RECT 49.745 153.790 49.815 154.000 ;
    END
  END rw0_rd_out[128]
  PIN rw0_rd_out[129]
    DIRECTION OUTPUT ;
    USE SIGNAL ;
    SHAPE ABUTMENT ;
    PORT
      LAYER metal2 ;
      RECT 50.125 153.790 50.195 154.000 ;
    END
  END rw0_rd_out[129]
  PIN rw0_rd_out[130]
    DIRECTION OUTPUT ;
    USE SIGNAL ;
    SHAPE ABUTMENT ;
    PORT
      LAYER metal2 ;
      RECT 50.505 153.790 50.575 154.000 ;
    END
  END rw0_rd_out[130]
  PIN rw0_rd_out[131]
    DIRECTION OUTPUT ;
    USE SIGNAL ;
    SHAPE ABUTMENT ;
    PORT
      LAYER metal2 ;
      RECT 50.885 153.790 50.955 154.000 ;
    END
  END rw0_rd_out[131]
  PIN rw0_rd_out[132]
    DIRECTION OUTPUT ;
    USE SIGNAL ;
    SHAPE ABUTMENT ;
    PORT
      LAYER metal2 ;
      RECT 51.265 153.790 51.335 154.000 ;
    END
  END rw0_rd_out[132]
  PIN rw0_rd_out[133]
    DIRECTION OUTPUT ;
    USE SIGNAL ;
    SHAPE ABUTMENT ;
    PORT
      LAYER metal2 ;
      RECT 51.645 153.790 51.715 154.000 ;
    END
  END rw0_rd_out[133]
  PIN rw0_rd_out[134]
    DIRECTION OUTPUT ;
    USE SIGNAL ;
    SHAPE ABUTMENT ;
    PORT
      LAYER metal2 ;
      RECT 52.025 153.790 52.095 154.000 ;
    END
  END rw0_rd_out[134]
  PIN rw0_rd_out[135]
    DIRECTION OUTPUT ;
    USE SIGNAL ;
    SHAPE ABUTMENT ;
    PORT
      LAYER metal2 ;
      RECT 52.405 153.790 52.475 154.000 ;
    END
  END rw0_rd_out[135]
  PIN rw0_rd_out[136]
    DIRECTION OUTPUT ;
    USE SIGNAL ;
    SHAPE ABUTMENT ;
    PORT
      LAYER metal2 ;
      RECT 52.785 153.790 52.855 154.000 ;
    END
  END rw0_rd_out[136]
  PIN rw0_rd_out[137]
    DIRECTION OUTPUT ;
    USE SIGNAL ;
    SHAPE ABUTMENT ;
    PORT
      LAYER metal2 ;
      RECT 53.165 153.790 53.235 154.000 ;
    END
  END rw0_rd_out[137]
  PIN rw0_rd_out[138]
    DIRECTION OUTPUT ;
    USE SIGNAL ;
    SHAPE ABUTMENT ;
    PORT
      LAYER metal2 ;
      RECT 53.545 153.790 53.615 154.000 ;
    END
  END rw0_rd_out[138]
  PIN rw0_rd_out[139]
    DIRECTION OUTPUT ;
    USE SIGNAL ;
    SHAPE ABUTMENT ;
    PORT
      LAYER metal2 ;
      RECT 53.925 153.790 53.995 154.000 ;
    END
  END rw0_rd_out[139]
  PIN rw0_rd_out[140]
    DIRECTION OUTPUT ;
    USE SIGNAL ;
    SHAPE ABUTMENT ;
    PORT
      LAYER metal2 ;
      RECT 54.305 153.790 54.375 154.000 ;
    END
  END rw0_rd_out[140]
  PIN rw0_rd_out[141]
    DIRECTION OUTPUT ;
    USE SIGNAL ;
    SHAPE ABUTMENT ;
    PORT
      LAYER metal2 ;
      RECT 54.685 153.790 54.755 154.000 ;
    END
  END rw0_rd_out[141]
  PIN rw0_rd_out[142]
    DIRECTION OUTPUT ;
    USE SIGNAL ;
    SHAPE ABUTMENT ;
    PORT
      LAYER metal2 ;
      RECT 55.065 153.790 55.135 154.000 ;
    END
  END rw0_rd_out[142]
  PIN rw0_rd_out[143]
    DIRECTION OUTPUT ;
    USE SIGNAL ;
    SHAPE ABUTMENT ;
    PORT
      LAYER metal2 ;
      RECT 55.445 153.790 55.515 154.000 ;
    END
  END rw0_rd_out[143]
  PIN rw0_rd_out[144]
    DIRECTION OUTPUT ;
    USE SIGNAL ;
    SHAPE ABUTMENT ;
    PORT
      LAYER metal2 ;
      RECT 55.825 153.790 55.895 154.000 ;
    END
  END rw0_rd_out[144]
  PIN rw0_rd_out[145]
    DIRECTION OUTPUT ;
    USE SIGNAL ;
    SHAPE ABUTMENT ;
    PORT
      LAYER metal2 ;
      RECT 56.205 153.790 56.275 154.000 ;
    END
  END rw0_rd_out[145]
  PIN rw0_rd_out[146]
    DIRECTION OUTPUT ;
    USE SIGNAL ;
    SHAPE ABUTMENT ;
    PORT
      LAYER metal2 ;
      RECT 56.585 153.790 56.655 154.000 ;
    END
  END rw0_rd_out[146]
  PIN rw0_rd_out[147]
    DIRECTION OUTPUT ;
    USE SIGNAL ;
    SHAPE ABUTMENT ;
    PORT
      LAYER metal2 ;
      RECT 56.965 153.790 57.035 154.000 ;
    END
  END rw0_rd_out[147]
  PIN rw0_rd_out[148]
    DIRECTION OUTPUT ;
    USE SIGNAL ;
    SHAPE ABUTMENT ;
    PORT
      LAYER metal2 ;
      RECT 57.345 153.790 57.415 154.000 ;
    END
  END rw0_rd_out[148]
  PIN rw0_rd_out[149]
    DIRECTION OUTPUT ;
    USE SIGNAL ;
    SHAPE ABUTMENT ;
    PORT
      LAYER metal2 ;
      RECT 57.725 153.790 57.795 154.000 ;
    END
  END rw0_rd_out[149]
  PIN rw0_rd_out[150]
    DIRECTION OUTPUT ;
    USE SIGNAL ;
    SHAPE ABUTMENT ;
    PORT
      LAYER metal2 ;
      RECT 58.105 153.790 58.175 154.000 ;
    END
  END rw0_rd_out[150]
  PIN rw0_rd_out[151]
    DIRECTION OUTPUT ;
    USE SIGNAL ;
    SHAPE ABUTMENT ;
    PORT
      LAYER metal2 ;
      RECT 58.485 153.790 58.555 154.000 ;
    END
  END rw0_rd_out[151]
  PIN rw0_rd_out[152]
    DIRECTION OUTPUT ;
    USE SIGNAL ;
    SHAPE ABUTMENT ;
    PORT
      LAYER metal2 ;
      RECT 58.865 153.790 58.935 154.000 ;
    END
  END rw0_rd_out[152]
  PIN rw0_rd_out[153]
    DIRECTION OUTPUT ;
    USE SIGNAL ;
    SHAPE ABUTMENT ;
    PORT
      LAYER metal2 ;
      RECT 59.245 153.790 59.315 154.000 ;
    END
  END rw0_rd_out[153]
  PIN rw0_rd_out[154]
    DIRECTION OUTPUT ;
    USE SIGNAL ;
    SHAPE ABUTMENT ;
    PORT
      LAYER metal2 ;
      RECT 59.625 153.790 59.695 154.000 ;
    END
  END rw0_rd_out[154]
  PIN rw0_rd_out[155]
    DIRECTION OUTPUT ;
    USE SIGNAL ;
    SHAPE ABUTMENT ;
    PORT
      LAYER metal2 ;
      RECT 60.005 153.790 60.075 154.000 ;
    END
  END rw0_rd_out[155]
  PIN rw0_rd_out[156]
    DIRECTION OUTPUT ;
    USE SIGNAL ;
    SHAPE ABUTMENT ;
    PORT
      LAYER metal2 ;
      RECT 60.385 153.790 60.455 154.000 ;
    END
  END rw0_rd_out[156]
  PIN rw0_rd_out[157]
    DIRECTION OUTPUT ;
    USE SIGNAL ;
    SHAPE ABUTMENT ;
    PORT
      LAYER metal2 ;
      RECT 60.765 153.790 60.835 154.000 ;
    END
  END rw0_rd_out[157]
  PIN rw0_rd_out[158]
    DIRECTION OUTPUT ;
    USE SIGNAL ;
    SHAPE ABUTMENT ;
    PORT
      LAYER metal2 ;
      RECT 61.145 153.790 61.215 154.000 ;
    END
  END rw0_rd_out[158]
  PIN rw0_rd_out[159]
    DIRECTION OUTPUT ;
    USE SIGNAL ;
    SHAPE ABUTMENT ;
    PORT
      LAYER metal2 ;
      RECT 61.525 153.790 61.595 154.000 ;
    END
  END rw0_rd_out[159]
  PIN rw0_rd_out[160]
    DIRECTION OUTPUT ;
    USE SIGNAL ;
    SHAPE ABUTMENT ;
    PORT
      LAYER metal2 ;
      RECT 61.905 153.790 61.975 154.000 ;
    END
  END rw0_rd_out[160]
  PIN rw0_rd_out[161]
    DIRECTION OUTPUT ;
    USE SIGNAL ;
    SHAPE ABUTMENT ;
    PORT
      LAYER metal2 ;
      RECT 62.285 153.790 62.355 154.000 ;
    END
  END rw0_rd_out[161]
  PIN rw0_rd_out[162]
    DIRECTION OUTPUT ;
    USE SIGNAL ;
    SHAPE ABUTMENT ;
    PORT
      LAYER metal2 ;
      RECT 62.665 153.790 62.735 154.000 ;
    END
  END rw0_rd_out[162]
  PIN rw0_rd_out[163]
    DIRECTION OUTPUT ;
    USE SIGNAL ;
    SHAPE ABUTMENT ;
    PORT
      LAYER metal2 ;
      RECT 63.045 153.790 63.115 154.000 ;
    END
  END rw0_rd_out[163]
  PIN rw0_rd_out[164]
    DIRECTION OUTPUT ;
    USE SIGNAL ;
    SHAPE ABUTMENT ;
    PORT
      LAYER metal2 ;
      RECT 63.425 153.790 63.495 154.000 ;
    END
  END rw0_rd_out[164]
  PIN rw0_rd_out[165]
    DIRECTION OUTPUT ;
    USE SIGNAL ;
    SHAPE ABUTMENT ;
    PORT
      LAYER metal2 ;
      RECT 63.805 153.790 63.875 154.000 ;
    END
  END rw0_rd_out[165]
  PIN rw0_rd_out[166]
    DIRECTION OUTPUT ;
    USE SIGNAL ;
    SHAPE ABUTMENT ;
    PORT
      LAYER metal2 ;
      RECT 64.185 153.790 64.255 154.000 ;
    END
  END rw0_rd_out[166]
  PIN rw0_rd_out[167]
    DIRECTION OUTPUT ;
    USE SIGNAL ;
    SHAPE ABUTMENT ;
    PORT
      LAYER metal2 ;
      RECT 64.565 153.790 64.635 154.000 ;
    END
  END rw0_rd_out[167]
  PIN rw0_rd_out[168]
    DIRECTION OUTPUT ;
    USE SIGNAL ;
    SHAPE ABUTMENT ;
    PORT
      LAYER metal2 ;
      RECT 64.945 153.790 65.015 154.000 ;
    END
  END rw0_rd_out[168]
  PIN rw0_rd_out[169]
    DIRECTION OUTPUT ;
    USE SIGNAL ;
    SHAPE ABUTMENT ;
    PORT
      LAYER metal2 ;
      RECT 65.325 153.790 65.395 154.000 ;
    END
  END rw0_rd_out[169]
  PIN rw0_rd_out[170]
    DIRECTION OUTPUT ;
    USE SIGNAL ;
    SHAPE ABUTMENT ;
    PORT
      LAYER metal2 ;
      RECT 65.705 153.790 65.775 154.000 ;
    END
  END rw0_rd_out[170]
  PIN rw0_rd_out[171]
    DIRECTION OUTPUT ;
    USE SIGNAL ;
    SHAPE ABUTMENT ;
    PORT
      LAYER metal2 ;
      RECT 66.085 153.790 66.155 154.000 ;
    END
  END rw0_rd_out[171]
  PIN rw0_rd_out[172]
    DIRECTION OUTPUT ;
    USE SIGNAL ;
    SHAPE ABUTMENT ;
    PORT
      LAYER metal2 ;
      RECT 66.465 153.790 66.535 154.000 ;
    END
  END rw0_rd_out[172]
  PIN rw0_rd_out[173]
    DIRECTION OUTPUT ;
    USE SIGNAL ;
    SHAPE ABUTMENT ;
    PORT
      LAYER metal2 ;
      RECT 66.845 153.790 66.915 154.000 ;
    END
  END rw0_rd_out[173]
  PIN rw0_rd_out[174]
    DIRECTION OUTPUT ;
    USE SIGNAL ;
    SHAPE ABUTMENT ;
    PORT
      LAYER metal2 ;
      RECT 67.225 153.790 67.295 154.000 ;
    END
  END rw0_rd_out[174]
  PIN rw0_rd_out[175]
    DIRECTION OUTPUT ;
    USE SIGNAL ;
    SHAPE ABUTMENT ;
    PORT
      LAYER metal2 ;
      RECT 67.605 153.790 67.675 154.000 ;
    END
  END rw0_rd_out[175]
  PIN rw0_rd_out[176]
    DIRECTION OUTPUT ;
    USE SIGNAL ;
    SHAPE ABUTMENT ;
    PORT
      LAYER metal2 ;
      RECT 67.985 153.790 68.055 154.000 ;
    END
  END rw0_rd_out[176]
  PIN rw0_rd_out[177]
    DIRECTION OUTPUT ;
    USE SIGNAL ;
    SHAPE ABUTMENT ;
    PORT
      LAYER metal2 ;
      RECT 68.365 153.790 68.435 154.000 ;
    END
  END rw0_rd_out[177]
  PIN rw0_rd_out[178]
    DIRECTION OUTPUT ;
    USE SIGNAL ;
    SHAPE ABUTMENT ;
    PORT
      LAYER metal2 ;
      RECT 68.745 153.790 68.815 154.000 ;
    END
  END rw0_rd_out[178]
  PIN rw0_rd_out[179]
    DIRECTION OUTPUT ;
    USE SIGNAL ;
    SHAPE ABUTMENT ;
    PORT
      LAYER metal2 ;
      RECT 69.125 153.790 69.195 154.000 ;
    END
  END rw0_rd_out[179]
  PIN rw0_rd_out[180]
    DIRECTION OUTPUT ;
    USE SIGNAL ;
    SHAPE ABUTMENT ;
    PORT
      LAYER metal2 ;
      RECT 69.505 153.790 69.575 154.000 ;
    END
  END rw0_rd_out[180]
  PIN rw0_rd_out[181]
    DIRECTION OUTPUT ;
    USE SIGNAL ;
    SHAPE ABUTMENT ;
    PORT
      LAYER metal2 ;
      RECT 69.885 153.790 69.955 154.000 ;
    END
  END rw0_rd_out[181]
  PIN rw0_rd_out[182]
    DIRECTION OUTPUT ;
    USE SIGNAL ;
    SHAPE ABUTMENT ;
    PORT
      LAYER metal2 ;
      RECT 70.265 153.790 70.335 154.000 ;
    END
  END rw0_rd_out[182]
  PIN rw0_rd_out[183]
    DIRECTION OUTPUT ;
    USE SIGNAL ;
    SHAPE ABUTMENT ;
    PORT
      LAYER metal2 ;
      RECT 70.645 153.790 70.715 154.000 ;
    END
  END rw0_rd_out[183]
  PIN rw0_addr_in[0]
    DIRECTION INPUT ;
    USE SIGNAL ;
    SHAPE ABUTMENT ;
    PORT
      LAYER metal3 ;
      RECT 0.000 142.485 0.210 142.555 ;
    END
  END rw0_addr_in[0]
  PIN rw0_addr_in[1]
    DIRECTION INPUT ;
    USE SIGNAL ;
    SHAPE ABUTMENT ;
    PORT
      LAYER metal3 ;
      RECT 0.000 144.025 0.210 144.095 ;
    END
  END rw0_addr_in[1]
  PIN rw0_addr_in[2]
    DIRECTION INPUT ;
    USE SIGNAL ;
    SHAPE ABUTMENT ;
    PORT
      LAYER metal3 ;
      RECT 0.000 145.565 0.210 145.635 ;
    END
  END rw0_addr_in[2]
  PIN rw0_addr_in[3]
    DIRECTION INPUT ;
    USE SIGNAL ;
    SHAPE ABUTMENT ;
    PORT
      LAYER metal3 ;
      RECT 92.700 142.485 92.910 142.555 ;
    END
  END rw0_addr_in[3]
  PIN rw0_addr_in[4]
    DIRECTION INPUT ;
    USE SIGNAL ;
    SHAPE ABUTMENT ;
    PORT
      LAYER metal3 ;
      RECT 92.700 144.025 92.910 144.095 ;
    END
  END rw0_addr_in[4]
  PIN rw0_addr_in[5]
    DIRECTION INPUT ;
    USE SIGNAL ;
    SHAPE ABUTMENT ;
    PORT
      LAYER metal3 ;
      RECT 92.700 145.565 92.910 145.635 ;
    END
  END rw0_addr_in[5]
  PIN rw0_we_in
    DIRECTION INPUT ;
    USE SIGNAL ;
    SHAPE ABUTMENT ;
    PORT
      LAYER metal2 ;
      RECT 71.025 153.790 71.095 154.000 ;
    END
  END rw0_we_in
  PIN rw0_ce_in
    DIRECTION INPUT ;
    USE SIGNAL ;
    SHAPE ABUTMENT ;
    PORT
      LAYER metal2 ;
      RECT 71.405 153.790 71.475 154.000 ;
    END
  END rw0_ce_in
  PIN rw0_clk
    DIRECTION INPUT ;
    USE SIGNAL ;
    SHAPE ABUTMENT ;
    PORT
      LAYER metal2 ;
      RECT 71.785 153.790 71.855 154.000 ;
    END
  END rw0_clk
  PIN VSS
    DIRECTION INOUT ;
    USE GROUND ;
    PORT
      LAYER metal4 ;
      RECT 1.000 0.840 1.280 153.160 ;
      RECT 3.240 0.840 3.520 153.160 ;
      RECT 5.480 0.840 5.760 153.160 ;
      RECT 7.720 0.840 8.000 153.160 ;
      RECT 9.960 0.840 10.240 153.160 ;
      RECT 12.200 0.840 12.480 153.160 ;
      RECT 14.440 0.840 14.720 153.160 ;
      RECT 16.680 0.840 16.960 153.160 ;
      RECT 18.920 0.840 19.200 153.160 ;
      RECT 21.160 0.840 21.440 153.160 ;
      RECT 23.400 0.840 23.680 153.160 ;
      RECT 25.640 0.840 25.920 153.160 ;
      RECT 27.880 0.840 28.160 153.160 ;
      RECT 30.120 0.840 30.400 153.160 ;
      RECT 32.360 0.840 32.640 153.160 ;
      RECT 34.600 0.840 34.880 153.160 ;
      RECT 36.840 0.840 37.120 153.160 ;
      RECT 39.080 0.840 39.360 153.160 ;
      RECT 41.320 0.840 41.600 153.160 ;
      RECT 43.560 0.840 43.840 153.160 ;
      RECT 45.800 0.840 46.080 153.160 ;
      RECT 48.040 0.840 48.320 153.160 ;
      RECT 50.280 0.840 50.560 153.160 ;
      RECT 52.520 0.840 52.800 153.160 ;
      RECT 54.760 0.840 55.040 153.160 ;
      RECT 57.000 0.840 57.280 153.160 ;
      RECT 59.240 0.840 59.520 153.160 ;
      RECT 61.480 0.840 61.760 153.160 ;
      RECT 63.720 0.840 64.000 153.160 ;
      RECT 65.960 0.840 66.240 153.160 ;
      RECT 68.200 0.840 68.480 153.160 ;
      RECT 70.440 0.840 70.720 153.160 ;
      RECT 72.680 0.840 72.960 153.160 ;
      RECT 74.920 0.840 75.200 153.160 ;
      RECT 77.160 0.840 77.440 153.160 ;
      RECT 79.400 0.840 79.680 153.160 ;
      RECT 81.640 0.840 81.920 153.160 ;
      RECT 83.880 0.840 84.160 153.160 ;
      RECT 86.120 0.840 86.400 153.160 ;
      RECT 88.360 0.840 88.640 153.160 ;
      RECT 90.600 0.840 90.880 153.160 ;
    END
  END VSS
  PIN VDD
    DIRECTION INOUT ;
    USE POWER ;
    PORT
      LAYER metal4 ;
      RECT 2.120 0.840 2.400 153.160 ;
      RECT 4.360 0.840 4.640 153.160 ;
      RECT 6.600 0.840 6.880 153.160 ;
      RECT 8.840 0.840 9.120 153.160 ;
      RECT 11.080 0.840 11.360 153.160 ;
      RECT 13.320 0.840 13.600 153.160 ;
      RECT 15.560 0.840 15.840 153.160 ;
      RECT 17.800 0.840 18.080 153.160 ;
      RECT 20.040 0.840 20.320 153.160 ;
      RECT 22.280 0.840 22.560 153.160 ;
      RECT 24.520 0.840 24.800 153.160 ;
      RECT 26.760 0.840 27.040 153.160 ;
      RECT 29.000 0.840 29.280 153.160 ;
      RECT 31.240 0.840 31.520 153.160 ;
      RECT 33.480 0.840 33.760 153.160 ;
      RECT 35.720 0.840 36.000 153.160 ;
      RECT 37.960 0.840 38.240 153.160 ;
      RECT 40.200 0.840 40.480 153.160 ;
      RECT 42.440 0.840 42.720 153.160 ;
      RECT 44.680 0.840 44.960 153.160 ;
      RECT 46.920 0.840 47.200 153.160 ;
      RECT 49.160 0.840 49.440 153.160 ;
      RECT 51.400 0.840 51.680 153.160 ;
      RECT 53.640 0.840 53.920 153.160 ;
      RECT 55.880 0.840 56.160 153.160 ;
      RECT 58.120 0.840 58.400 153.160 ;
      RECT 60.360 0.840 60.640 153.160 ;
      RECT 62.600 0.840 62.880 153.160 ;
      RECT 64.840 0.840 65.120 153.160 ;
      RECT 67.080 0.840 67.360 153.160 ;
      RECT 69.320 0.840 69.600 153.160 ;
      RECT 71.560 0.840 71.840 153.160 ;
      RECT 73.800 0.840 74.080 153.160 ;
      RECT 76.040 0.840 76.320 153.160 ;
      RECT 78.280 0.840 78.560 153.160 ;
      RECT 80.520 0.840 80.800 153.160 ;
      RECT 82.760 0.840 83.040 153.160 ;
      RECT 85.000 0.840 85.280 153.160 ;
      RECT 87.240 0.840 87.520 153.160 ;
      RECT 89.480 0.840 89.760 153.160 ;
      RECT 91.720 0.840 92.000 153.160 ;
    END
  END VDD
  OBS
    LAYER metal1 ;
    RECT 0 0 92.910 154.000 ;
    LAYER metal2 ;
    RECT 0 0 92.910 154.000 ;
    LAYER metal3 ;
    RECT 0 0 92.910 154.000 ;
    LAYER metal4 ;
    RECT 0 0 92.910 154.000 ;
    LAYER OVERLAP ;
    RECT 0 0 92.910 154.000 ;
  END
END fakeram_64x184_1rw

END LIBRARY
